# OpenTallas memory compiler (tools/mem_compiler), ASAP7 abstract view, track-aligned v2 (build_aligned_v2.py)
VERSION 5.7 ;
BUSBITCHARS "[]" ;
DIVIDERCHAR "/" ;
PROPERTYDEFINITIONS
  MACRO width INTEGER ;
  MACRO depth INTEGER ;
  MACRO banks INTEGER ;
END PROPERTYDEFINITIONS
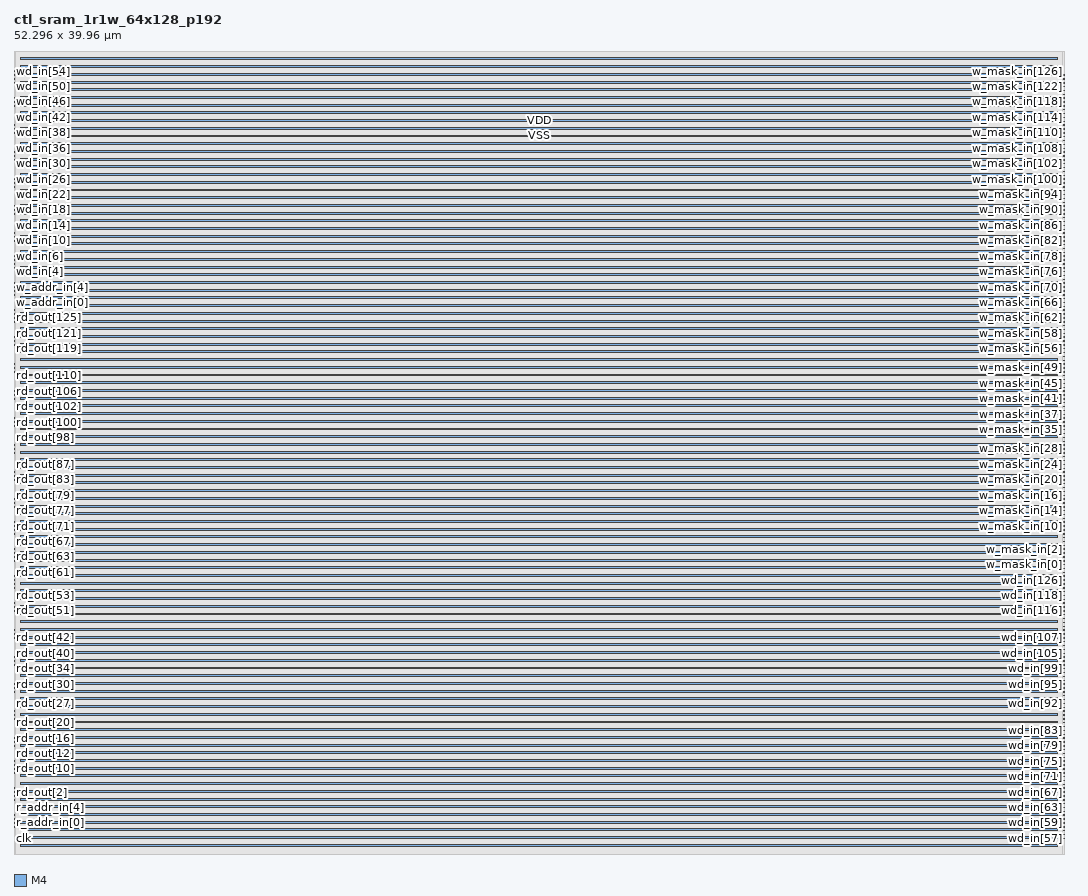
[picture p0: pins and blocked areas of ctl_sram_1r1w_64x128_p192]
MACRO ctl_sram_1r1w_64x128_p192
  PROPERTY width 128 ;
  PROPERTY depth 64 ;
  PROPERTY banks 1 ;
  FOREIGN ctl_sram_1r1w_64x128_p192 0 0 ;
  SYMMETRY X Y ;
  SIZE 52.296 BY 39.960 ;
  CLASS BLOCK ;
  PIN clk
    DIRECTION INPUT ;
    USE CLOCK ;
    SHAPE ABUTMENT ;
    PORT
      LAYER M4 ;
      RECT 0.000 0.768 0.024 0.792 ;
    END
  END clk
  PIN r_ce_in
    DIRECTION INPUT ;
    USE SIGNAL ;
    SHAPE ABUTMENT ;
    PORT
      LAYER M4 ;
      RECT 0.000 0.960 0.024 0.984 ;
    END
  END r_ce_in
  PIN r_addr_in[0]
    DIRECTION INPUT ;
    USE SIGNAL ;
    SHAPE ABUTMENT ;
    PORT
      LAYER M4 ;
      RECT 0.000 1.152 0.024 1.176 ;
    END
  END r_addr_in[0]
  PIN r_addr_in[1]
    DIRECTION INPUT ;
    USE SIGNAL ;
    SHAPE ABUTMENT ;
    PORT
      LAYER M4 ;
      RECT 0.000 1.344 0.024 1.368 ;
    END
  END r_addr_in[1]
  PIN r_addr_in[2]
    DIRECTION INPUT ;
    USE SIGNAL ;
    SHAPE ABUTMENT ;
    PORT
      LAYER M4 ;
      RECT 0.000 1.536 0.024 1.560 ;
    END
  END r_addr_in[2]
  PIN r_addr_in[3]
    DIRECTION INPUT ;
    USE SIGNAL ;
    SHAPE ABUTMENT ;
    PORT
      LAYER M4 ;
      RECT 0.000 1.728 0.024 1.752 ;
    END
  END r_addr_in[3]
  PIN r_addr_in[4]
    DIRECTION INPUT ;
    USE SIGNAL ;
    SHAPE ABUTMENT ;
    PORT
      LAYER M4 ;
      RECT 0.000 1.920 0.024 1.944 ;
    END
  END r_addr_in[4]
  PIN r_addr_in[5]
    DIRECTION INPUT ;
    USE SIGNAL ;
    SHAPE ABUTMENT ;
    PORT
      LAYER M4 ;
      RECT 0.000 2.112 0.024 2.136 ;
    END
  END r_addr_in[5]
  PIN rd_out[0]
    DIRECTION OUTPUT ;
    USE SIGNAL ;
    SHAPE ABUTMENT ;
    PORT
      LAYER M4 ;
      RECT 0.000 2.304 0.024 2.328 ;
    END
  END rd_out[0]
  PIN rd_out[1]
    DIRECTION OUTPUT ;
    USE SIGNAL ;
    SHAPE ABUTMENT ;
    PORT
      LAYER M4 ;
      RECT 0.000 2.496 0.024 2.520 ;
    END
  END rd_out[1]
  PIN rd_out[2]
    DIRECTION OUTPUT ;
    USE SIGNAL ;
    SHAPE ABUTMENT ;
    PORT
      LAYER M4 ;
      RECT 0.000 2.688 0.024 2.712 ;
    END
  END rd_out[2]
  PIN rd_out[3]
    DIRECTION OUTPUT ;
    USE SIGNAL ;
    SHAPE ABUTMENT ;
    PORT
      LAYER M4 ;
      RECT 0.000 2.880 0.024 2.904 ;
    END
  END rd_out[3]
  PIN rd_out[4]
    DIRECTION OUTPUT ;
    USE SIGNAL ;
    SHAPE ABUTMENT ;
    PORT
      LAYER M4 ;
      RECT 0.000 3.072 0.024 3.096 ;
    END
  END rd_out[4]
  PIN rd_out[5]
    DIRECTION OUTPUT ;
    USE SIGNAL ;
    SHAPE ABUTMENT ;
    PORT
      LAYER M4 ;
      RECT 0.000 3.264 0.024 3.288 ;
    END
  END rd_out[5]
  PIN rd_out[6]
    DIRECTION OUTPUT ;
    USE SIGNAL ;
    SHAPE ABUTMENT ;
    PORT
      LAYER M4 ;
      RECT 0.000 3.456 0.024 3.480 ;
    END
  END rd_out[6]
  PIN rd_out[7]
    DIRECTION OUTPUT ;
    USE SIGNAL ;
    SHAPE ABUTMENT ;
    PORT
      LAYER M4 ;
      RECT 0.000 3.648 0.024 3.672 ;
    END
  END rd_out[7]
  PIN rd_out[8]
    DIRECTION OUTPUT ;
    USE SIGNAL ;
    SHAPE ABUTMENT ;
    PORT
      LAYER M4 ;
      RECT 0.000 3.840 0.024 3.864 ;
    END
  END rd_out[8]
  PIN rd_out[9]
    DIRECTION OUTPUT ;
    USE SIGNAL ;
    SHAPE ABUTMENT ;
    PORT
      LAYER M4 ;
      RECT 0.000 4.032 0.024 4.056 ;
    END
  END rd_out[9]
  PIN rd_out[10]
    DIRECTION OUTPUT ;
    USE SIGNAL ;
    SHAPE ABUTMENT ;
    PORT
      LAYER M4 ;
      RECT 0.000 4.224 0.024 4.248 ;
    END
  END rd_out[10]
  PIN rd_out[11]
    DIRECTION OUTPUT ;
    USE SIGNAL ;
    SHAPE ABUTMENT ;
    PORT
      LAYER M4 ;
      RECT 0.000 4.416 0.024 4.440 ;
    END
  END rd_out[11]
  PIN rd_out[12]
    DIRECTION OUTPUT ;
    USE SIGNAL ;
    SHAPE ABUTMENT ;
    PORT
      LAYER M4 ;
      RECT 0.000 4.608 0.024 4.632 ;
    END
  END rd_out[12]
  PIN rd_out[13]
    DIRECTION OUTPUT ;
    USE SIGNAL ;
    SHAPE ABUTMENT ;
    PORT
      LAYER M4 ;
      RECT 0.000 4.800 0.024 4.824 ;
    END
  END rd_out[13]
  PIN rd_out[14]
    DIRECTION OUTPUT ;
    USE SIGNAL ;
    SHAPE ABUTMENT ;
    PORT
      LAYER M4 ;
      RECT 0.000 4.992 0.024 5.016 ;
    END
  END rd_out[14]
  PIN rd_out[15]
    DIRECTION OUTPUT ;
    USE SIGNAL ;
    SHAPE ABUTMENT ;
    PORT
      LAYER M4 ;
      RECT 0.000 5.184 0.024 5.208 ;
    END
  END rd_out[15]
  PIN rd_out[16]
    DIRECTION OUTPUT ;
    USE SIGNAL ;
    SHAPE ABUTMENT ;
    PORT
      LAYER M4 ;
      RECT 0.000 5.376 0.024 5.400 ;
    END
  END rd_out[16]
  PIN rd_out[17]
    DIRECTION OUTPUT ;
    USE SIGNAL ;
    SHAPE ABUTMENT ;
    PORT
      LAYER M4 ;
      RECT 0.000 5.568 0.024 5.592 ;
    END
  END rd_out[17]
  PIN rd_out[18]
    DIRECTION OUTPUT ;
    USE SIGNAL ;
    SHAPE ABUTMENT ;
    PORT
      LAYER M4 ;
      RECT 0.000 5.760 0.024 5.784 ;
    END
  END rd_out[18]
  PIN rd_out[19]
    DIRECTION OUTPUT ;
    USE SIGNAL ;
    SHAPE ABUTMENT ;
    PORT
      LAYER M4 ;
      RECT 0.000 5.952 0.024 5.976 ;
    END
  END rd_out[19]
  PIN rd_out[20]
    DIRECTION OUTPUT ;
    USE SIGNAL ;
    SHAPE ABUTMENT ;
    PORT
      LAYER M4 ;
      RECT 0.000 6.144 0.024 6.168 ;
    END
  END rd_out[20]
  PIN rd_out[21]
    DIRECTION OUTPUT ;
    USE SIGNAL ;
    SHAPE ABUTMENT ;
    PORT
      LAYER M4 ;
      RECT 0.000 6.336 0.024 6.360 ;
    END
  END rd_out[21]
  PIN rd_out[22]
    DIRECTION OUTPUT ;
    USE SIGNAL ;
    SHAPE ABUTMENT ;
    PORT
      LAYER M4 ;
      RECT 0.000 6.528 0.024 6.552 ;
    END
  END rd_out[22]
  PIN rd_out[23]
    DIRECTION OUTPUT ;
    USE SIGNAL ;
    SHAPE ABUTMENT ;
    PORT
      LAYER M4 ;
      RECT 0.000 6.720 0.024 6.744 ;
    END
  END rd_out[23]
  PIN rd_out[24]
    DIRECTION OUTPUT ;
    USE SIGNAL ;
    SHAPE ABUTMENT ;
    PORT
      LAYER M4 ;
      RECT 0.000 6.912 0.024 6.936 ;
    END
  END rd_out[24]
  PIN rd_out[25]
    DIRECTION OUTPUT ;
    USE SIGNAL ;
    SHAPE ABUTMENT ;
    PORT
      LAYER M4 ;
      RECT 0.000 7.104 0.024 7.128 ;
    END
  END rd_out[25]
  PIN rd_out[26]
    DIRECTION OUTPUT ;
    USE SIGNAL ;
    SHAPE ABUTMENT ;
    PORT
      LAYER M4 ;
      RECT 0.000 7.296 0.024 7.320 ;
    END
  END rd_out[26]
  PIN rd_out[27]
    DIRECTION OUTPUT ;
    USE SIGNAL ;
    SHAPE ABUTMENT ;
    PORT
      LAYER M4 ;
      RECT 0.000 7.488 0.024 7.512 ;
    END
  END rd_out[27]
  PIN rd_out[28]
    DIRECTION OUTPUT ;
    USE SIGNAL ;
    SHAPE ABUTMENT ;
    PORT
      LAYER M4 ;
      RECT 0.000 7.680 0.024 7.704 ;
    END
  END rd_out[28]
  PIN rd_out[29]
    DIRECTION OUTPUT ;
    USE SIGNAL ;
    SHAPE ABUTMENT ;
    PORT
      LAYER M4 ;
      RECT 0.000 7.872 0.024 7.896 ;
    END
  END rd_out[29]
  PIN rd_out[30]
    DIRECTION OUTPUT ;
    USE SIGNAL ;
    SHAPE ABUTMENT ;
    PORT
      LAYER M4 ;
      RECT 0.000 8.064 0.024 8.088 ;
    END
  END rd_out[30]
  PIN rd_out[31]
    DIRECTION OUTPUT ;
    USE SIGNAL ;
    SHAPE ABUTMENT ;
    PORT
      LAYER M4 ;
      RECT 0.000 8.256 0.024 8.280 ;
    END
  END rd_out[31]
  PIN rd_out[32]
    DIRECTION OUTPUT ;
    USE SIGNAL ;
    SHAPE ABUTMENT ;
    PORT
      LAYER M4 ;
      RECT 0.000 8.448 0.024 8.472 ;
    END
  END rd_out[32]
  PIN rd_out[33]
    DIRECTION OUTPUT ;
    USE SIGNAL ;
    SHAPE ABUTMENT ;
    PORT
      LAYER M4 ;
      RECT 0.000 8.640 0.024 8.664 ;
    END
  END rd_out[33]
  PIN rd_out[34]
    DIRECTION OUTPUT ;
    USE SIGNAL ;
    SHAPE ABUTMENT ;
    PORT
      LAYER M4 ;
      RECT 0.000 8.832 0.024 8.856 ;
    END
  END rd_out[34]
  PIN rd_out[35]
    DIRECTION OUTPUT ;
    USE SIGNAL ;
    SHAPE ABUTMENT ;
    PORT
      LAYER M4 ;
      RECT 0.000 9.024 0.024 9.048 ;
    END
  END rd_out[35]
  PIN rd_out[36]
    DIRECTION OUTPUT ;
    USE SIGNAL ;
    SHAPE ABUTMENT ;
    PORT
      LAYER M4 ;
      RECT 0.000 9.216 0.024 9.240 ;
    END
  END rd_out[36]
  PIN rd_out[37]
    DIRECTION OUTPUT ;
    USE SIGNAL ;
    SHAPE ABUTMENT ;
    PORT
      LAYER M4 ;
      RECT 0.000 9.408 0.024 9.432 ;
    END
  END rd_out[37]
  PIN rd_out[38]
    DIRECTION OUTPUT ;
    USE SIGNAL ;
    SHAPE ABUTMENT ;
    PORT
      LAYER M4 ;
      RECT 0.000 9.600 0.024 9.624 ;
    END
  END rd_out[38]
  PIN rd_out[39]
    DIRECTION OUTPUT ;
    USE SIGNAL ;
    SHAPE ABUTMENT ;
    PORT
      LAYER M4 ;
      RECT 0.000 9.792 0.024 9.816 ;
    END
  END rd_out[39]
  PIN rd_out[40]
    DIRECTION OUTPUT ;
    USE SIGNAL ;
    SHAPE ABUTMENT ;
    PORT
      LAYER M4 ;
      RECT 0.000 9.984 0.024 10.008 ;
    END
  END rd_out[40]
  PIN rd_out[41]
    DIRECTION OUTPUT ;
    USE SIGNAL ;
    SHAPE ABUTMENT ;
    PORT
      LAYER M4 ;
      RECT 0.000 10.176 0.024 10.200 ;
    END
  END rd_out[41]
  PIN rd_out[42]
    DIRECTION OUTPUT ;
    USE SIGNAL ;
    SHAPE ABUTMENT ;
    PORT
      LAYER M4 ;
      RECT 0.000 10.368 0.024 10.392 ;
    END
  END rd_out[42]
  PIN rd_out[43]
    DIRECTION OUTPUT ;
    USE SIGNAL ;
    SHAPE ABUTMENT ;
    PORT
      LAYER M4 ;
      RECT 0.000 10.560 0.024 10.584 ;
    END
  END rd_out[43]
  PIN rd_out[44]
    DIRECTION OUTPUT ;
    USE SIGNAL ;
    SHAPE ABUTMENT ;
    PORT
      LAYER M4 ;
      RECT 0.000 10.752 0.024 10.776 ;
    END
  END rd_out[44]
  PIN rd_out[45]
    DIRECTION OUTPUT ;
    USE SIGNAL ;
    SHAPE ABUTMENT ;
    PORT
      LAYER M4 ;
      RECT 0.000 10.944 0.024 10.968 ;
    END
  END rd_out[45]
  PIN rd_out[46]
    DIRECTION OUTPUT ;
    USE SIGNAL ;
    SHAPE ABUTMENT ;
    PORT
      LAYER M4 ;
      RECT 0.000 11.136 0.024 11.160 ;
    END
  END rd_out[46]
  PIN rd_out[47]
    DIRECTION OUTPUT ;
    USE SIGNAL ;
    SHAPE ABUTMENT ;
    PORT
      LAYER M4 ;
      RECT 0.000 11.328 0.024 11.352 ;
    END
  END rd_out[47]
  PIN rd_out[48]
    DIRECTION OUTPUT ;
    USE SIGNAL ;
    SHAPE ABUTMENT ;
    PORT
      LAYER M4 ;
      RECT 0.000 11.520 0.024 11.544 ;
    END
  END rd_out[48]
  PIN rd_out[49]
    DIRECTION OUTPUT ;
    USE SIGNAL ;
    SHAPE ABUTMENT ;
    PORT
      LAYER M4 ;
      RECT 0.000 11.712 0.024 11.736 ;
    END
  END rd_out[49]
  PIN rd_out[50]
    DIRECTION OUTPUT ;
    USE SIGNAL ;
    SHAPE ABUTMENT ;
    PORT
      LAYER M4 ;
      RECT 0.000 11.904 0.024 11.928 ;
    END
  END rd_out[50]
  PIN rd_out[51]
    DIRECTION OUTPUT ;
    USE SIGNAL ;
    SHAPE ABUTMENT ;
    PORT
      LAYER M4 ;
      RECT 0.000 12.096 0.024 12.120 ;
    END
  END rd_out[51]
  PIN rd_out[52]
    DIRECTION OUTPUT ;
    USE SIGNAL ;
    SHAPE ABUTMENT ;
    PORT
      LAYER M4 ;
      RECT 0.000 12.288 0.024 12.312 ;
    END
  END rd_out[52]
  PIN rd_out[53]
    DIRECTION OUTPUT ;
    USE SIGNAL ;
    SHAPE ABUTMENT ;
    PORT
      LAYER M4 ;
      RECT 0.000 12.480 0.024 12.504 ;
    END
  END rd_out[53]
  PIN rd_out[54]
    DIRECTION OUTPUT ;
    USE SIGNAL ;
    SHAPE ABUTMENT ;
    PORT
      LAYER M4 ;
      RECT 0.000 12.672 0.024 12.696 ;
    END
  END rd_out[54]
  PIN rd_out[55]
    DIRECTION OUTPUT ;
    USE SIGNAL ;
    SHAPE ABUTMENT ;
    PORT
      LAYER M4 ;
      RECT 0.000 12.864 0.024 12.888 ;
    END
  END rd_out[55]
  PIN rd_out[56]
    DIRECTION OUTPUT ;
    USE SIGNAL ;
    SHAPE ABUTMENT ;
    PORT
      LAYER M4 ;
      RECT 0.000 13.056 0.024 13.080 ;
    END
  END rd_out[56]
  PIN rd_out[57]
    DIRECTION OUTPUT ;
    USE SIGNAL ;
    SHAPE ABUTMENT ;
    PORT
      LAYER M4 ;
      RECT 0.000 13.248 0.024 13.272 ;
    END
  END rd_out[57]
  PIN rd_out[58]
    DIRECTION OUTPUT ;
    USE SIGNAL ;
    SHAPE ABUTMENT ;
    PORT
      LAYER M4 ;
      RECT 0.000 13.440 0.024 13.464 ;
    END
  END rd_out[58]
  PIN rd_out[59]
    DIRECTION OUTPUT ;
    USE SIGNAL ;
    SHAPE ABUTMENT ;
    PORT
      LAYER M4 ;
      RECT 0.000 13.632 0.024 13.656 ;
    END
  END rd_out[59]
  PIN rd_out[60]
    DIRECTION OUTPUT ;
    USE SIGNAL ;
    SHAPE ABUTMENT ;
    PORT
      LAYER M4 ;
      RECT 0.000 13.824 0.024 13.848 ;
    END
  END rd_out[60]
  PIN rd_out[61]
    DIRECTION OUTPUT ;
    USE SIGNAL ;
    SHAPE ABUTMENT ;
    PORT
      LAYER M4 ;
      RECT 0.000 14.016 0.024 14.040 ;
    END
  END rd_out[61]
  PIN rd_out[62]
    DIRECTION OUTPUT ;
    USE SIGNAL ;
    SHAPE ABUTMENT ;
    PORT
      LAYER M4 ;
      RECT 0.000 14.208 0.024 14.232 ;
    END
  END rd_out[62]
  PIN rd_out[63]
    DIRECTION OUTPUT ;
    USE SIGNAL ;
    SHAPE ABUTMENT ;
    PORT
      LAYER M4 ;
      RECT 0.000 14.400 0.024 14.424 ;
    END
  END rd_out[63]
  PIN rd_out[64]
    DIRECTION OUTPUT ;
    USE SIGNAL ;
    SHAPE ABUTMENT ;
    PORT
      LAYER M4 ;
      RECT 0.000 14.592 0.024 14.616 ;
    END
  END rd_out[64]
  PIN rd_out[65]
    DIRECTION OUTPUT ;
    USE SIGNAL ;
    SHAPE ABUTMENT ;
    PORT
      LAYER M4 ;
      RECT 0.000 14.784 0.024 14.808 ;
    END
  END rd_out[65]
  PIN rd_out[66]
    DIRECTION OUTPUT ;
    USE SIGNAL ;
    SHAPE ABUTMENT ;
    PORT
      LAYER M4 ;
      RECT 0.000 14.976 0.024 15.000 ;
    END
  END rd_out[66]
  PIN rd_out[67]
    DIRECTION OUTPUT ;
    USE SIGNAL ;
    SHAPE ABUTMENT ;
    PORT
      LAYER M4 ;
      RECT 0.000 15.168 0.024 15.192 ;
    END
  END rd_out[67]
  PIN rd_out[68]
    DIRECTION OUTPUT ;
    USE SIGNAL ;
    SHAPE ABUTMENT ;
    PORT
      LAYER M4 ;
      RECT 0.000 15.360 0.024 15.384 ;
    END
  END rd_out[68]
  PIN rd_out[69]
    DIRECTION OUTPUT ;
    USE SIGNAL ;
    SHAPE ABUTMENT ;
    PORT
      LAYER M4 ;
      RECT 0.000 15.552 0.024 15.576 ;
    END
  END rd_out[69]
  PIN rd_out[70]
    DIRECTION OUTPUT ;
    USE SIGNAL ;
    SHAPE ABUTMENT ;
    PORT
      LAYER M4 ;
      RECT 0.000 15.744 0.024 15.768 ;
    END
  END rd_out[70]
  PIN rd_out[71]
    DIRECTION OUTPUT ;
    USE SIGNAL ;
    SHAPE ABUTMENT ;
    PORT
      LAYER M4 ;
      RECT 0.000 15.936 0.024 15.960 ;
    END
  END rd_out[71]
  PIN rd_out[72]
    DIRECTION OUTPUT ;
    USE SIGNAL ;
    SHAPE ABUTMENT ;
    PORT
      LAYER M4 ;
      RECT 0.000 16.128 0.024 16.152 ;
    END
  END rd_out[72]
  PIN rd_out[73]
    DIRECTION OUTPUT ;
    USE SIGNAL ;
    SHAPE ABUTMENT ;
    PORT
      LAYER M4 ;
      RECT 0.000 16.320 0.024 16.344 ;
    END
  END rd_out[73]
  PIN rd_out[74]
    DIRECTION OUTPUT ;
    USE SIGNAL ;
    SHAPE ABUTMENT ;
    PORT
      LAYER M4 ;
      RECT 0.000 16.512 0.024 16.536 ;
    END
  END rd_out[74]
  PIN rd_out[75]
    DIRECTION OUTPUT ;
    USE SIGNAL ;
    SHAPE ABUTMENT ;
    PORT
      LAYER M4 ;
      RECT 0.000 16.704 0.024 16.728 ;
    END
  END rd_out[75]
  PIN rd_out[76]
    DIRECTION OUTPUT ;
    USE SIGNAL ;
    SHAPE ABUTMENT ;
    PORT
      LAYER M4 ;
      RECT 0.000 16.896 0.024 16.920 ;
    END
  END rd_out[76]
  PIN rd_out[77]
    DIRECTION OUTPUT ;
    USE SIGNAL ;
    SHAPE ABUTMENT ;
    PORT
      LAYER M4 ;
      RECT 0.000 17.088 0.024 17.112 ;
    END
  END rd_out[77]
  PIN rd_out[78]
    DIRECTION OUTPUT ;
    USE SIGNAL ;
    SHAPE ABUTMENT ;
    PORT
      LAYER M4 ;
      RECT 0.000 17.280 0.024 17.304 ;
    END
  END rd_out[78]
  PIN rd_out[79]
    DIRECTION OUTPUT ;
    USE SIGNAL ;
    SHAPE ABUTMENT ;
    PORT
      LAYER M4 ;
      RECT 0.000 17.472 0.024 17.496 ;
    END
  END rd_out[79]
  PIN rd_out[80]
    DIRECTION OUTPUT ;
    USE SIGNAL ;
    SHAPE ABUTMENT ;
    PORT
      LAYER M4 ;
      RECT 0.000 17.664 0.024 17.688 ;
    END
  END rd_out[80]
  PIN rd_out[81]
    DIRECTION OUTPUT ;
    USE SIGNAL ;
    SHAPE ABUTMENT ;
    PORT
      LAYER M4 ;
      RECT 0.000 17.856 0.024 17.880 ;
    END
  END rd_out[81]
  PIN rd_out[82]
    DIRECTION OUTPUT ;
    USE SIGNAL ;
    SHAPE ABUTMENT ;
    PORT
      LAYER M4 ;
      RECT 0.000 18.048 0.024 18.072 ;
    END
  END rd_out[82]
  PIN rd_out[83]
    DIRECTION OUTPUT ;
    USE SIGNAL ;
    SHAPE ABUTMENT ;
    PORT
      LAYER M4 ;
      RECT 0.000 18.240 0.024 18.264 ;
    END
  END rd_out[83]
  PIN rd_out[84]
    DIRECTION OUTPUT ;
    USE SIGNAL ;
    SHAPE ABUTMENT ;
    PORT
      LAYER M4 ;
      RECT 0.000 18.432 0.024 18.456 ;
    END
  END rd_out[84]
  PIN rd_out[85]
    DIRECTION OUTPUT ;
    USE SIGNAL ;
    SHAPE ABUTMENT ;
    PORT
      LAYER M4 ;
      RECT 0.000 18.624 0.024 18.648 ;
    END
  END rd_out[85]
  PIN rd_out[86]
    DIRECTION OUTPUT ;
    USE SIGNAL ;
    SHAPE ABUTMENT ;
    PORT
      LAYER M4 ;
      RECT 0.000 18.816 0.024 18.840 ;
    END
  END rd_out[86]
  PIN rd_out[87]
    DIRECTION OUTPUT ;
    USE SIGNAL ;
    SHAPE ABUTMENT ;
    PORT
      LAYER M4 ;
      RECT 0.000 19.008 0.024 19.032 ;
    END
  END rd_out[87]
  PIN rd_out[88]
    DIRECTION OUTPUT ;
    USE SIGNAL ;
    SHAPE ABUTMENT ;
    PORT
      LAYER M4 ;
      RECT 0.000 19.200 0.024 19.224 ;
    END
  END rd_out[88]
  PIN rd_out[89]
    DIRECTION OUTPUT ;
    USE SIGNAL ;
    SHAPE ABUTMENT ;
    PORT
      LAYER M4 ;
      RECT 0.000 19.392 0.024 19.416 ;
    END
  END rd_out[89]
  PIN rd_out[90]
    DIRECTION OUTPUT ;
    USE SIGNAL ;
    SHAPE ABUTMENT ;
    PORT
      LAYER M4 ;
      RECT 0.000 19.584 0.024 19.608 ;
    END
  END rd_out[90]
  PIN rd_out[91]
    DIRECTION OUTPUT ;
    USE SIGNAL ;
    SHAPE ABUTMENT ;
    PORT
      LAYER M4 ;
      RECT 0.000 19.776 0.024 19.800 ;
    END
  END rd_out[91]
  PIN rd_out[92]
    DIRECTION OUTPUT ;
    USE SIGNAL ;
    SHAPE ABUTMENT ;
    PORT
      LAYER M4 ;
      RECT 0.000 19.968 0.024 19.992 ;
    END
  END rd_out[92]
  PIN rd_out[93]
    DIRECTION OUTPUT ;
    USE SIGNAL ;
    SHAPE ABUTMENT ;
    PORT
      LAYER M4 ;
      RECT 0.000 20.160 0.024 20.184 ;
    END
  END rd_out[93]
  PIN rd_out[94]
    DIRECTION OUTPUT ;
    USE SIGNAL ;
    SHAPE ABUTMENT ;
    PORT
      LAYER M4 ;
      RECT 0.000 20.352 0.024 20.376 ;
    END
  END rd_out[94]
  PIN rd_out[95]
    DIRECTION OUTPUT ;
    USE SIGNAL ;
    SHAPE ABUTMENT ;
    PORT
      LAYER M4 ;
      RECT 0.000 20.544 0.024 20.568 ;
    END
  END rd_out[95]
  PIN rd_out[96]
    DIRECTION OUTPUT ;
    USE SIGNAL ;
    SHAPE ABUTMENT ;
    PORT
      LAYER M4 ;
      RECT 0.000 20.736 0.024 20.760 ;
    END
  END rd_out[96]
  PIN rd_out[97]
    DIRECTION OUTPUT ;
    USE SIGNAL ;
    SHAPE ABUTMENT ;
    PORT
      LAYER M4 ;
      RECT 0.000 20.928 0.024 20.952 ;
    END
  END rd_out[97]
  PIN rd_out[98]
    DIRECTION OUTPUT ;
    USE SIGNAL ;
    SHAPE ABUTMENT ;
    PORT
      LAYER M4 ;
      RECT 0.000 21.120 0.024 21.144 ;
    END
  END rd_out[98]
  PIN rd_out[99]
    DIRECTION OUTPUT ;
    USE SIGNAL ;
    SHAPE ABUTMENT ;
    PORT
      LAYER M4 ;
      RECT 0.000 21.312 0.024 21.336 ;
    END
  END rd_out[99]
  PIN rd_out[100]
    DIRECTION OUTPUT ;
    USE SIGNAL ;
    SHAPE ABUTMENT ;
    PORT
      LAYER M4 ;
      RECT 0.000 21.504 0.024 21.528 ;
    END
  END rd_out[100]
  PIN rd_out[101]
    DIRECTION OUTPUT ;
    USE SIGNAL ;
    SHAPE ABUTMENT ;
    PORT
      LAYER M4 ;
      RECT 0.000 21.696 0.024 21.720 ;
    END
  END rd_out[101]
  PIN rd_out[102]
    DIRECTION OUTPUT ;
    USE SIGNAL ;
    SHAPE ABUTMENT ;
    PORT
      LAYER M4 ;
      RECT 0.000 21.888 0.024 21.912 ;
    END
  END rd_out[102]
  PIN rd_out[103]
    DIRECTION OUTPUT ;
    USE SIGNAL ;
    SHAPE ABUTMENT ;
    PORT
      LAYER M4 ;
      RECT 0.000 22.080 0.024 22.104 ;
    END
  END rd_out[103]
  PIN rd_out[104]
    DIRECTION OUTPUT ;
    USE SIGNAL ;
    SHAPE ABUTMENT ;
    PORT
      LAYER M4 ;
      RECT 0.000 22.272 0.024 22.296 ;
    END
  END rd_out[104]
  PIN rd_out[105]
    DIRECTION OUTPUT ;
    USE SIGNAL ;
    SHAPE ABUTMENT ;
    PORT
      LAYER M4 ;
      RECT 0.000 22.464 0.024 22.488 ;
    END
  END rd_out[105]
  PIN rd_out[106]
    DIRECTION OUTPUT ;
    USE SIGNAL ;
    SHAPE ABUTMENT ;
    PORT
      LAYER M4 ;
      RECT 0.000 22.656 0.024 22.680 ;
    END
  END rd_out[106]
  PIN rd_out[107]
    DIRECTION OUTPUT ;
    USE SIGNAL ;
    SHAPE ABUTMENT ;
    PORT
      LAYER M4 ;
      RECT 0.000 22.848 0.024 22.872 ;
    END
  END rd_out[107]
  PIN rd_out[108]
    DIRECTION OUTPUT ;
    USE SIGNAL ;
    SHAPE ABUTMENT ;
    PORT
      LAYER M4 ;
      RECT 0.000 23.040 0.024 23.064 ;
    END
  END rd_out[108]
  PIN rd_out[109]
    DIRECTION OUTPUT ;
    USE SIGNAL ;
    SHAPE ABUTMENT ;
    PORT
      LAYER M4 ;
      RECT 0.000 23.232 0.024 23.256 ;
    END
  END rd_out[109]
  PIN rd_out[110]
    DIRECTION OUTPUT ;
    USE SIGNAL ;
    SHAPE ABUTMENT ;
    PORT
      LAYER M4 ;
      RECT 0.000 23.424 0.024 23.448 ;
    END
  END rd_out[110]
  PIN rd_out[111]
    DIRECTION OUTPUT ;
    USE SIGNAL ;
    SHAPE ABUTMENT ;
    PORT
      LAYER M4 ;
      RECT 0.000 23.616 0.024 23.640 ;
    END
  END rd_out[111]
  PIN rd_out[112]
    DIRECTION OUTPUT ;
    USE SIGNAL ;
    SHAPE ABUTMENT ;
    PORT
      LAYER M4 ;
      RECT 0.000 23.808 0.024 23.832 ;
    END
  END rd_out[112]
  PIN rd_out[113]
    DIRECTION OUTPUT ;
    USE SIGNAL ;
    SHAPE ABUTMENT ;
    PORT
      LAYER M4 ;
      RECT 0.000 24.000 0.024 24.024 ;
    END
  END rd_out[113]
  PIN rd_out[114]
    DIRECTION OUTPUT ;
    USE SIGNAL ;
    SHAPE ABUTMENT ;
    PORT
      LAYER M4 ;
      RECT 0.000 24.192 0.024 24.216 ;
    END
  END rd_out[114]
  PIN rd_out[115]
    DIRECTION OUTPUT ;
    USE SIGNAL ;
    SHAPE ABUTMENT ;
    PORT
      LAYER M4 ;
      RECT 0.000 24.384 0.024 24.408 ;
    END
  END rd_out[115]
  PIN rd_out[116]
    DIRECTION OUTPUT ;
    USE SIGNAL ;
    SHAPE ABUTMENT ;
    PORT
      LAYER M4 ;
      RECT 0.000 24.576 0.024 24.600 ;
    END
  END rd_out[116]
  PIN rd_out[117]
    DIRECTION OUTPUT ;
    USE SIGNAL ;
    SHAPE ABUTMENT ;
    PORT
      LAYER M4 ;
      RECT 0.000 24.768 0.024 24.792 ;
    END
  END rd_out[117]
  PIN rd_out[118]
    DIRECTION OUTPUT ;
    USE SIGNAL ;
    SHAPE ABUTMENT ;
    PORT
      LAYER M4 ;
      RECT 0.000 24.960 0.024 24.984 ;
    END
  END rd_out[118]
  PIN rd_out[119]
    DIRECTION OUTPUT ;
    USE SIGNAL ;
    SHAPE ABUTMENT ;
    PORT
      LAYER M4 ;
      RECT 0.000 25.152 0.024 25.176 ;
    END
  END rd_out[119]
  PIN rd_out[120]
    DIRECTION OUTPUT ;
    USE SIGNAL ;
    SHAPE ABUTMENT ;
    PORT
      LAYER M4 ;
      RECT 0.000 25.344 0.024 25.368 ;
    END
  END rd_out[120]
  PIN rd_out[121]
    DIRECTION OUTPUT ;
    USE SIGNAL ;
    SHAPE ABUTMENT ;
    PORT
      LAYER M4 ;
      RECT 0.000 25.536 0.024 25.560 ;
    END
  END rd_out[121]
  PIN rd_out[122]
    DIRECTION OUTPUT ;
    USE SIGNAL ;
    SHAPE ABUTMENT ;
    PORT
      LAYER M4 ;
      RECT 0.000 25.728 0.024 25.752 ;
    END
  END rd_out[122]
  PIN rd_out[123]
    DIRECTION OUTPUT ;
    USE SIGNAL ;
    SHAPE ABUTMENT ;
    PORT
      LAYER M4 ;
      RECT 0.000 25.920 0.024 25.944 ;
    END
  END rd_out[123]
  PIN rd_out[124]
    DIRECTION OUTPUT ;
    USE SIGNAL ;
    SHAPE ABUTMENT ;
    PORT
      LAYER M4 ;
      RECT 0.000 26.112 0.024 26.136 ;
    END
  END rd_out[124]
  PIN rd_out[125]
    DIRECTION OUTPUT ;
    USE SIGNAL ;
    SHAPE ABUTMENT ;
    PORT
      LAYER M4 ;
      RECT 0.000 26.304 0.024 26.328 ;
    END
  END rd_out[125]
  PIN rd_out[126]
    DIRECTION OUTPUT ;
    USE SIGNAL ;
    SHAPE ABUTMENT ;
    PORT
      LAYER M4 ;
      RECT 0.000 26.496 0.024 26.520 ;
    END
  END rd_out[126]
  PIN rd_out[127]
    DIRECTION OUTPUT ;
    USE SIGNAL ;
    SHAPE ABUTMENT ;
    PORT
      LAYER M4 ;
      RECT 0.000 26.688 0.024 26.712 ;
    END
  END rd_out[127]
  PIN w_ce_in
    DIRECTION INPUT ;
    USE SIGNAL ;
    SHAPE ABUTMENT ;
    PORT
      LAYER M4 ;
      RECT 0.000 26.880 0.024 26.904 ;
    END
  END w_ce_in
  PIN w_addr_in[0]
    DIRECTION INPUT ;
    USE SIGNAL ;
    SHAPE ABUTMENT ;
    PORT
      LAYER M4 ;
      RECT 0.000 27.072 0.024 27.096 ;
    END
  END w_addr_in[0]
  PIN w_addr_in[1]
    DIRECTION INPUT ;
    USE SIGNAL ;
    SHAPE ABUTMENT ;
    PORT
      LAYER M4 ;
      RECT 0.000 27.264 0.024 27.288 ;
    END
  END w_addr_in[1]
  PIN w_addr_in[2]
    DIRECTION INPUT ;
    USE SIGNAL ;
    SHAPE ABUTMENT ;
    PORT
      LAYER M4 ;
      RECT 0.000 27.456 0.024 27.480 ;
    END
  END w_addr_in[2]
  PIN w_addr_in[3]
    DIRECTION INPUT ;
    USE SIGNAL ;
    SHAPE ABUTMENT ;
    PORT
      LAYER M4 ;
      RECT 0.000 27.648 0.024 27.672 ;
    END
  END w_addr_in[3]
  PIN w_addr_in[4]
    DIRECTION INPUT ;
    USE SIGNAL ;
    SHAPE ABUTMENT ;
    PORT
      LAYER M4 ;
      RECT 0.000 27.840 0.024 27.864 ;
    END
  END w_addr_in[4]
  PIN w_addr_in[5]
    DIRECTION INPUT ;
    USE SIGNAL ;
    SHAPE ABUTMENT ;
    PORT
      LAYER M4 ;
      RECT 0.000 28.032 0.024 28.056 ;
    END
  END w_addr_in[5]
  PIN wd_in[0]
    DIRECTION INPUT ;
    USE SIGNAL ;
    SHAPE ABUTMENT ;
    PORT
      LAYER M4 ;
      RECT 0.000 28.224 0.024 28.248 ;
    END
  END wd_in[0]
  PIN wd_in[1]
    DIRECTION INPUT ;
    USE SIGNAL ;
    SHAPE ABUTMENT ;
    PORT
      LAYER M4 ;
      RECT 0.000 28.416 0.024 28.440 ;
    END
  END wd_in[1]
  PIN wd_in[2]
    DIRECTION INPUT ;
    USE SIGNAL ;
    SHAPE ABUTMENT ;
    PORT
      LAYER M4 ;
      RECT 0.000 28.608 0.024 28.632 ;
    END
  END wd_in[2]
  PIN wd_in[3]
    DIRECTION INPUT ;
    USE SIGNAL ;
    SHAPE ABUTMENT ;
    PORT
      LAYER M4 ;
      RECT 0.000 28.800 0.024 28.824 ;
    END
  END wd_in[3]
  PIN wd_in[4]
    DIRECTION INPUT ;
    USE SIGNAL ;
    SHAPE ABUTMENT ;
    PORT
      LAYER M4 ;
      RECT 0.000 28.992 0.024 29.016 ;
    END
  END wd_in[4]
  PIN wd_in[5]
    DIRECTION INPUT ;
    USE SIGNAL ;
    SHAPE ABUTMENT ;
    PORT
      LAYER M4 ;
      RECT 0.000 29.184 0.024 29.208 ;
    END
  END wd_in[5]
  PIN wd_in[6]
    DIRECTION INPUT ;
    USE SIGNAL ;
    SHAPE ABUTMENT ;
    PORT
      LAYER M4 ;
      RECT 0.000 29.376 0.024 29.400 ;
    END
  END wd_in[6]
  PIN wd_in[7]
    DIRECTION INPUT ;
    USE SIGNAL ;
    SHAPE ABUTMENT ;
    PORT
      LAYER M4 ;
      RECT 0.000 29.568 0.024 29.592 ;
    END
  END wd_in[7]
  PIN wd_in[8]
    DIRECTION INPUT ;
    USE SIGNAL ;
    SHAPE ABUTMENT ;
    PORT
      LAYER M4 ;
      RECT 0.000 29.760 0.024 29.784 ;
    END
  END wd_in[8]
  PIN wd_in[9]
    DIRECTION INPUT ;
    USE SIGNAL ;
    SHAPE ABUTMENT ;
    PORT
      LAYER M4 ;
      RECT 0.000 29.952 0.024 29.976 ;
    END
  END wd_in[9]
  PIN wd_in[10]
    DIRECTION INPUT ;
    USE SIGNAL ;
    SHAPE ABUTMENT ;
    PORT
      LAYER M4 ;
      RECT 0.000 30.144 0.024 30.168 ;
    END
  END wd_in[10]
  PIN wd_in[11]
    DIRECTION INPUT ;
    USE SIGNAL ;
    SHAPE ABUTMENT ;
    PORT
      LAYER M4 ;
      RECT 0.000 30.336 0.024 30.360 ;
    END
  END wd_in[11]
  PIN wd_in[12]
    DIRECTION INPUT ;
    USE SIGNAL ;
    SHAPE ABUTMENT ;
    PORT
      LAYER M4 ;
      RECT 0.000 30.528 0.024 30.552 ;
    END
  END wd_in[12]
  PIN wd_in[13]
    DIRECTION INPUT ;
    USE SIGNAL ;
    SHAPE ABUTMENT ;
    PORT
      LAYER M4 ;
      RECT 0.000 30.720 0.024 30.744 ;
    END
  END wd_in[13]
  PIN wd_in[14]
    DIRECTION INPUT ;
    USE SIGNAL ;
    SHAPE ABUTMENT ;
    PORT
      LAYER M4 ;
      RECT 0.000 30.912 0.024 30.936 ;
    END
  END wd_in[14]
  PIN wd_in[15]
    DIRECTION INPUT ;
    USE SIGNAL ;
    SHAPE ABUTMENT ;
    PORT
      LAYER M4 ;
      RECT 0.000 31.104 0.024 31.128 ;
    END
  END wd_in[15]
  PIN wd_in[16]
    DIRECTION INPUT ;
    USE SIGNAL ;
    SHAPE ABUTMENT ;
    PORT
      LAYER M4 ;
      RECT 0.000 31.296 0.024 31.320 ;
    END
  END wd_in[16]
  PIN wd_in[17]
    DIRECTION INPUT ;
    USE SIGNAL ;
    SHAPE ABUTMENT ;
    PORT
      LAYER M4 ;
      RECT 0.000 31.488 0.024 31.512 ;
    END
  END wd_in[17]
  PIN wd_in[18]
    DIRECTION INPUT ;
    USE SIGNAL ;
    SHAPE ABUTMENT ;
    PORT
      LAYER M4 ;
      RECT 0.000 31.680 0.024 31.704 ;
    END
  END wd_in[18]
  PIN wd_in[19]
    DIRECTION INPUT ;
    USE SIGNAL ;
    SHAPE ABUTMENT ;
    PORT
      LAYER M4 ;
      RECT 0.000 31.872 0.024 31.896 ;
    END
  END wd_in[19]
  PIN wd_in[20]
    DIRECTION INPUT ;
    USE SIGNAL ;
    SHAPE ABUTMENT ;
    PORT
      LAYER M4 ;
      RECT 0.000 32.064 0.024 32.088 ;
    END
  END wd_in[20]
  PIN wd_in[21]
    DIRECTION INPUT ;
    USE SIGNAL ;
    SHAPE ABUTMENT ;
    PORT
      LAYER M4 ;
      RECT 0.000 32.256 0.024 32.280 ;
    END
  END wd_in[21]
  PIN wd_in[22]
    DIRECTION INPUT ;
    USE SIGNAL ;
    SHAPE ABUTMENT ;
    PORT
      LAYER M4 ;
      RECT 0.000 32.448 0.024 32.472 ;
    END
  END wd_in[22]
  PIN wd_in[23]
    DIRECTION INPUT ;
    USE SIGNAL ;
    SHAPE ABUTMENT ;
    PORT
      LAYER M4 ;
      RECT 0.000 32.640 0.024 32.664 ;
    END
  END wd_in[23]
  PIN wd_in[24]
    DIRECTION INPUT ;
    USE SIGNAL ;
    SHAPE ABUTMENT ;
    PORT
      LAYER M4 ;
      RECT 0.000 32.832 0.024 32.856 ;
    END
  END wd_in[24]
  PIN wd_in[25]
    DIRECTION INPUT ;
    USE SIGNAL ;
    SHAPE ABUTMENT ;
    PORT
      LAYER M4 ;
      RECT 0.000 33.024 0.024 33.048 ;
    END
  END wd_in[25]
  PIN wd_in[26]
    DIRECTION INPUT ;
    USE SIGNAL ;
    SHAPE ABUTMENT ;
    PORT
      LAYER M4 ;
      RECT 0.000 33.216 0.024 33.240 ;
    END
  END wd_in[26]
  PIN wd_in[27]
    DIRECTION INPUT ;
    USE SIGNAL ;
    SHAPE ABUTMENT ;
    PORT
      LAYER M4 ;
      RECT 0.000 33.408 0.024 33.432 ;
    END
  END wd_in[27]
  PIN wd_in[28]
    DIRECTION INPUT ;
    USE SIGNAL ;
    SHAPE ABUTMENT ;
    PORT
      LAYER M4 ;
      RECT 0.000 33.600 0.024 33.624 ;
    END
  END wd_in[28]
  PIN wd_in[29]
    DIRECTION INPUT ;
    USE SIGNAL ;
    SHAPE ABUTMENT ;
    PORT
      LAYER M4 ;
      RECT 0.000 33.792 0.024 33.816 ;
    END
  END wd_in[29]
  PIN wd_in[30]
    DIRECTION INPUT ;
    USE SIGNAL ;
    SHAPE ABUTMENT ;
    PORT
      LAYER M4 ;
      RECT 0.000 33.984 0.024 34.008 ;
    END
  END wd_in[30]
  PIN wd_in[31]
    DIRECTION INPUT ;
    USE SIGNAL ;
    SHAPE ABUTMENT ;
    PORT
      LAYER M4 ;
      RECT 0.000 34.176 0.024 34.200 ;
    END
  END wd_in[31]
  PIN wd_in[32]
    DIRECTION INPUT ;
    USE SIGNAL ;
    SHAPE ABUTMENT ;
    PORT
      LAYER M4 ;
      RECT 0.000 34.368 0.024 34.392 ;
    END
  END wd_in[32]
  PIN wd_in[33]
    DIRECTION INPUT ;
    USE SIGNAL ;
    SHAPE ABUTMENT ;
    PORT
      LAYER M4 ;
      RECT 0.000 34.560 0.024 34.584 ;
    END
  END wd_in[33]
  PIN wd_in[34]
    DIRECTION INPUT ;
    USE SIGNAL ;
    SHAPE ABUTMENT ;
    PORT
      LAYER M4 ;
      RECT 0.000 34.752 0.024 34.776 ;
    END
  END wd_in[34]
  PIN wd_in[35]
    DIRECTION INPUT ;
    USE SIGNAL ;
    SHAPE ABUTMENT ;
    PORT
      LAYER M4 ;
      RECT 0.000 34.944 0.024 34.968 ;
    END
  END wd_in[35]
  PIN wd_in[36]
    DIRECTION INPUT ;
    USE SIGNAL ;
    SHAPE ABUTMENT ;
    PORT
      LAYER M4 ;
      RECT 0.000 35.136 0.024 35.160 ;
    END
  END wd_in[36]
  PIN wd_in[37]
    DIRECTION INPUT ;
    USE SIGNAL ;
    SHAPE ABUTMENT ;
    PORT
      LAYER M4 ;
      RECT 0.000 35.328 0.024 35.352 ;
    END
  END wd_in[37]
  PIN wd_in[38]
    DIRECTION INPUT ;
    USE SIGNAL ;
    SHAPE ABUTMENT ;
    PORT
      LAYER M4 ;
      RECT 0.000 35.520 0.024 35.544 ;
    END
  END wd_in[38]
  PIN wd_in[39]
    DIRECTION INPUT ;
    USE SIGNAL ;
    SHAPE ABUTMENT ;
    PORT
      LAYER M4 ;
      RECT 0.000 35.712 0.024 35.736 ;
    END
  END wd_in[39]
  PIN wd_in[40]
    DIRECTION INPUT ;
    USE SIGNAL ;
    SHAPE ABUTMENT ;
    PORT
      LAYER M4 ;
      RECT 0.000 35.904 0.024 35.928 ;
    END
  END wd_in[40]
  PIN wd_in[41]
    DIRECTION INPUT ;
    USE SIGNAL ;
    SHAPE ABUTMENT ;
    PORT
      LAYER M4 ;
      RECT 0.000 36.096 0.024 36.120 ;
    END
  END wd_in[41]
  PIN wd_in[42]
    DIRECTION INPUT ;
    USE SIGNAL ;
    SHAPE ABUTMENT ;
    PORT
      LAYER M4 ;
      RECT 0.000 36.288 0.024 36.312 ;
    END
  END wd_in[42]
  PIN wd_in[43]
    DIRECTION INPUT ;
    USE SIGNAL ;
    SHAPE ABUTMENT ;
    PORT
      LAYER M4 ;
      RECT 0.000 36.480 0.024 36.504 ;
    END
  END wd_in[43]
  PIN wd_in[44]
    DIRECTION INPUT ;
    USE SIGNAL ;
    SHAPE ABUTMENT ;
    PORT
      LAYER M4 ;
      RECT 0.000 36.672 0.024 36.696 ;
    END
  END wd_in[44]
  PIN wd_in[45]
    DIRECTION INPUT ;
    USE SIGNAL ;
    SHAPE ABUTMENT ;
    PORT
      LAYER M4 ;
      RECT 0.000 36.864 0.024 36.888 ;
    END
  END wd_in[45]
  PIN wd_in[46]
    DIRECTION INPUT ;
    USE SIGNAL ;
    SHAPE ABUTMENT ;
    PORT
      LAYER M4 ;
      RECT 0.000 37.056 0.024 37.080 ;
    END
  END wd_in[46]
  PIN wd_in[47]
    DIRECTION INPUT ;
    USE SIGNAL ;
    SHAPE ABUTMENT ;
    PORT
      LAYER M4 ;
      RECT 0.000 37.248 0.024 37.272 ;
    END
  END wd_in[47]
  PIN wd_in[48]
    DIRECTION INPUT ;
    USE SIGNAL ;
    SHAPE ABUTMENT ;
    PORT
      LAYER M4 ;
      RECT 0.000 37.440 0.024 37.464 ;
    END
  END wd_in[48]
  PIN wd_in[49]
    DIRECTION INPUT ;
    USE SIGNAL ;
    SHAPE ABUTMENT ;
    PORT
      LAYER M4 ;
      RECT 0.000 37.632 0.024 37.656 ;
    END
  END wd_in[49]
  PIN wd_in[50]
    DIRECTION INPUT ;
    USE SIGNAL ;
    SHAPE ABUTMENT ;
    PORT
      LAYER M4 ;
      RECT 0.000 37.824 0.024 37.848 ;
    END
  END wd_in[50]
  PIN wd_in[51]
    DIRECTION INPUT ;
    USE SIGNAL ;
    SHAPE ABUTMENT ;
    PORT
      LAYER M4 ;
      RECT 0.000 38.016 0.024 38.040 ;
    END
  END wd_in[51]
  PIN wd_in[52]
    DIRECTION INPUT ;
    USE SIGNAL ;
    SHAPE ABUTMENT ;
    PORT
      LAYER M4 ;
      RECT 0.000 38.208 0.024 38.232 ;
    END
  END wd_in[52]
  PIN wd_in[53]
    DIRECTION INPUT ;
    USE SIGNAL ;
    SHAPE ABUTMENT ;
    PORT
      LAYER M4 ;
      RECT 0.000 38.400 0.024 38.424 ;
    END
  END wd_in[53]
  PIN wd_in[54]
    DIRECTION INPUT ;
    USE SIGNAL ;
    SHAPE ABUTMENT ;
    PORT
      LAYER M4 ;
      RECT 0.000 38.592 0.024 38.616 ;
    END
  END wd_in[54]
  PIN wd_in[55]
    DIRECTION INPUT ;
    USE SIGNAL ;
    SHAPE ABUTMENT ;
    PORT
      LAYER M4 ;
      RECT 0.000 38.784 0.024 38.808 ;
    END
  END wd_in[55]
  PIN wd_in[56]
    DIRECTION INPUT ;
    USE SIGNAL ;
    SHAPE ABUTMENT ;
    PORT
      LAYER M4 ;
      RECT 0.000 38.976 0.024 39.000 ;
    END
  END wd_in[56]
  PIN wd_in[57]
    DIRECTION INPUT ;
    USE SIGNAL ;
    SHAPE ABUTMENT ;
    PORT
      LAYER M4 ;
      RECT 52.272 0.768 52.296 0.792 ;
    END
  END wd_in[57]
  PIN wd_in[58]
    DIRECTION INPUT ;
    USE SIGNAL ;
    SHAPE ABUTMENT ;
    PORT
      LAYER M4 ;
      RECT 52.272 0.960 52.296 0.984 ;
    END
  END wd_in[58]
  PIN wd_in[59]
    DIRECTION INPUT ;
    USE SIGNAL ;
    SHAPE ABUTMENT ;
    PORT
      LAYER M4 ;
      RECT 52.272 1.152 52.296 1.176 ;
    END
  END wd_in[59]
  PIN wd_in[60]
    DIRECTION INPUT ;
    USE SIGNAL ;
    SHAPE ABUTMENT ;
    PORT
      LAYER M4 ;
      RECT 52.272 1.344 52.296 1.368 ;
    END
  END wd_in[60]
  PIN wd_in[61]
    DIRECTION INPUT ;
    USE SIGNAL ;
    SHAPE ABUTMENT ;
    PORT
      LAYER M4 ;
      RECT 52.272 1.536 52.296 1.560 ;
    END
  END wd_in[61]
  PIN wd_in[62]
    DIRECTION INPUT ;
    USE SIGNAL ;
    SHAPE ABUTMENT ;
    PORT
      LAYER M4 ;
      RECT 52.272 1.728 52.296 1.752 ;
    END
  END wd_in[62]
  PIN wd_in[63]
    DIRECTION INPUT ;
    USE SIGNAL ;
    SHAPE ABUTMENT ;
    PORT
      LAYER M4 ;
      RECT 52.272 1.920 52.296 1.944 ;
    END
  END wd_in[63]
  PIN wd_in[64]
    DIRECTION INPUT ;
    USE SIGNAL ;
    SHAPE ABUTMENT ;
    PORT
      LAYER M4 ;
      RECT 52.272 2.112 52.296 2.136 ;
    END
  END wd_in[64]
  PIN wd_in[65]
    DIRECTION INPUT ;
    USE SIGNAL ;
    SHAPE ABUTMENT ;
    PORT
      LAYER M4 ;
      RECT 52.272 2.304 52.296 2.328 ;
    END
  END wd_in[65]
  PIN wd_in[66]
    DIRECTION INPUT ;
    USE SIGNAL ;
    SHAPE ABUTMENT ;
    PORT
      LAYER M4 ;
      RECT 52.272 2.496 52.296 2.520 ;
    END
  END wd_in[66]
  PIN wd_in[67]
    DIRECTION INPUT ;
    USE SIGNAL ;
    SHAPE ABUTMENT ;
    PORT
      LAYER M4 ;
      RECT 52.272 2.688 52.296 2.712 ;
    END
  END wd_in[67]
  PIN wd_in[68]
    DIRECTION INPUT ;
    USE SIGNAL ;
    SHAPE ABUTMENT ;
    PORT
      LAYER M4 ;
      RECT 52.272 2.880 52.296 2.904 ;
    END
  END wd_in[68]
  PIN wd_in[69]
    DIRECTION INPUT ;
    USE SIGNAL ;
    SHAPE ABUTMENT ;
    PORT
      LAYER M4 ;
      RECT 52.272 3.072 52.296 3.096 ;
    END
  END wd_in[69]
  PIN wd_in[70]
    DIRECTION INPUT ;
    USE SIGNAL ;
    SHAPE ABUTMENT ;
    PORT
      LAYER M4 ;
      RECT 52.272 3.264 52.296 3.288 ;
    END
  END wd_in[70]
  PIN wd_in[71]
    DIRECTION INPUT ;
    USE SIGNAL ;
    SHAPE ABUTMENT ;
    PORT
      LAYER M4 ;
      RECT 52.272 3.456 52.296 3.480 ;
    END
  END wd_in[71]
  PIN wd_in[72]
    DIRECTION INPUT ;
    USE SIGNAL ;
    SHAPE ABUTMENT ;
    PORT
      LAYER M4 ;
      RECT 52.272 3.648 52.296 3.672 ;
    END
  END wd_in[72]
  PIN wd_in[73]
    DIRECTION INPUT ;
    USE SIGNAL ;
    SHAPE ABUTMENT ;
    PORT
      LAYER M4 ;
      RECT 52.272 3.840 52.296 3.864 ;
    END
  END wd_in[73]
  PIN wd_in[74]
    DIRECTION INPUT ;
    USE SIGNAL ;
    SHAPE ABUTMENT ;
    PORT
      LAYER M4 ;
      RECT 52.272 4.032 52.296 4.056 ;
    END
  END wd_in[74]
  PIN wd_in[75]
    DIRECTION INPUT ;
    USE SIGNAL ;
    SHAPE ABUTMENT ;
    PORT
      LAYER M4 ;
      RECT 52.272 4.224 52.296 4.248 ;
    END
  END wd_in[75]
  PIN wd_in[76]
    DIRECTION INPUT ;
    USE SIGNAL ;
    SHAPE ABUTMENT ;
    PORT
      LAYER M4 ;
      RECT 52.272 4.416 52.296 4.440 ;
    END
  END wd_in[76]
  PIN wd_in[77]
    DIRECTION INPUT ;
    USE SIGNAL ;
    SHAPE ABUTMENT ;
    PORT
      LAYER M4 ;
      RECT 52.272 4.608 52.296 4.632 ;
    END
  END wd_in[77]
  PIN wd_in[78]
    DIRECTION INPUT ;
    USE SIGNAL ;
    SHAPE ABUTMENT ;
    PORT
      LAYER M4 ;
      RECT 52.272 4.800 52.296 4.824 ;
    END
  END wd_in[78]
  PIN wd_in[79]
    DIRECTION INPUT ;
    USE SIGNAL ;
    SHAPE ABUTMENT ;
    PORT
      LAYER M4 ;
      RECT 52.272 4.992 52.296 5.016 ;
    END
  END wd_in[79]
  PIN wd_in[80]
    DIRECTION INPUT ;
    USE SIGNAL ;
    SHAPE ABUTMENT ;
    PORT
      LAYER M4 ;
      RECT 52.272 5.184 52.296 5.208 ;
    END
  END wd_in[80]
  PIN wd_in[81]
    DIRECTION INPUT ;
    USE SIGNAL ;
    SHAPE ABUTMENT ;
    PORT
      LAYER M4 ;
      RECT 52.272 5.376 52.296 5.400 ;
    END
  END wd_in[81]
  PIN wd_in[82]
    DIRECTION INPUT ;
    USE SIGNAL ;
    SHAPE ABUTMENT ;
    PORT
      LAYER M4 ;
      RECT 52.272 5.568 52.296 5.592 ;
    END
  END wd_in[82]
  PIN wd_in[83]
    DIRECTION INPUT ;
    USE SIGNAL ;
    SHAPE ABUTMENT ;
    PORT
      LAYER M4 ;
      RECT 52.272 5.760 52.296 5.784 ;
    END
  END wd_in[83]
  PIN wd_in[84]
    DIRECTION INPUT ;
    USE SIGNAL ;
    SHAPE ABUTMENT ;
    PORT
      LAYER M4 ;
      RECT 52.272 5.952 52.296 5.976 ;
    END
  END wd_in[84]
  PIN wd_in[85]
    DIRECTION INPUT ;
    USE SIGNAL ;
    SHAPE ABUTMENT ;
    PORT
      LAYER M4 ;
      RECT 52.272 6.144 52.296 6.168 ;
    END
  END wd_in[85]
  PIN wd_in[86]
    DIRECTION INPUT ;
    USE SIGNAL ;
    SHAPE ABUTMENT ;
    PORT
      LAYER M4 ;
      RECT 52.272 6.336 52.296 6.360 ;
    END
  END wd_in[86]
  PIN wd_in[87]
    DIRECTION INPUT ;
    USE SIGNAL ;
    SHAPE ABUTMENT ;
    PORT
      LAYER M4 ;
      RECT 52.272 6.528 52.296 6.552 ;
    END
  END wd_in[87]
  PIN wd_in[88]
    DIRECTION INPUT ;
    USE SIGNAL ;
    SHAPE ABUTMENT ;
    PORT
      LAYER M4 ;
      RECT 52.272 6.720 52.296 6.744 ;
    END
  END wd_in[88]
  PIN wd_in[89]
    DIRECTION INPUT ;
    USE SIGNAL ;
    SHAPE ABUTMENT ;
    PORT
      LAYER M4 ;
      RECT 52.272 6.912 52.296 6.936 ;
    END
  END wd_in[89]
  PIN wd_in[90]
    DIRECTION INPUT ;
    USE SIGNAL ;
    SHAPE ABUTMENT ;
    PORT
      LAYER M4 ;
      RECT 52.272 7.104 52.296 7.128 ;
    END
  END wd_in[90]
  PIN wd_in[91]
    DIRECTION INPUT ;
    USE SIGNAL ;
    SHAPE ABUTMENT ;
    PORT
      LAYER M4 ;
      RECT 52.272 7.296 52.296 7.320 ;
    END
  END wd_in[91]
  PIN wd_in[92]
    DIRECTION INPUT ;
    USE SIGNAL ;
    SHAPE ABUTMENT ;
    PORT
      LAYER M4 ;
      RECT 52.272 7.488 52.296 7.512 ;
    END
  END wd_in[92]
  PIN wd_in[93]
    DIRECTION INPUT ;
    USE SIGNAL ;
    SHAPE ABUTMENT ;
    PORT
      LAYER M4 ;
      RECT 52.272 7.680 52.296 7.704 ;
    END
  END wd_in[93]
  PIN wd_in[94]
    DIRECTION INPUT ;
    USE SIGNAL ;
    SHAPE ABUTMENT ;
    PORT
      LAYER M4 ;
      RECT 52.272 7.872 52.296 7.896 ;
    END
  END wd_in[94]
  PIN wd_in[95]
    DIRECTION INPUT ;
    USE SIGNAL ;
    SHAPE ABUTMENT ;
    PORT
      LAYER M4 ;
      RECT 52.272 8.064 52.296 8.088 ;
    END
  END wd_in[95]
  PIN wd_in[96]
    DIRECTION INPUT ;
    USE SIGNAL ;
    SHAPE ABUTMENT ;
    PORT
      LAYER M4 ;
      RECT 52.272 8.256 52.296 8.280 ;
    END
  END wd_in[96]
  PIN wd_in[97]
    DIRECTION INPUT ;
    USE SIGNAL ;
    SHAPE ABUTMENT ;
    PORT
      LAYER M4 ;
      RECT 52.272 8.448 52.296 8.472 ;
    END
  END wd_in[97]
  PIN wd_in[98]
    DIRECTION INPUT ;
    USE SIGNAL ;
    SHAPE ABUTMENT ;
    PORT
      LAYER M4 ;
      RECT 52.272 8.640 52.296 8.664 ;
    END
  END wd_in[98]
  PIN wd_in[99]
    DIRECTION INPUT ;
    USE SIGNAL ;
    SHAPE ABUTMENT ;
    PORT
      LAYER M4 ;
      RECT 52.272 8.832 52.296 8.856 ;
    END
  END wd_in[99]
  PIN wd_in[100]
    DIRECTION INPUT ;
    USE SIGNAL ;
    SHAPE ABUTMENT ;
    PORT
      LAYER M4 ;
      RECT 52.272 9.024 52.296 9.048 ;
    END
  END wd_in[100]
  PIN wd_in[101]
    DIRECTION INPUT ;
    USE SIGNAL ;
    SHAPE ABUTMENT ;
    PORT
      LAYER M4 ;
      RECT 52.272 9.216 52.296 9.240 ;
    END
  END wd_in[101]
  PIN wd_in[102]
    DIRECTION INPUT ;
    USE SIGNAL ;
    SHAPE ABUTMENT ;
    PORT
      LAYER M4 ;
      RECT 52.272 9.408 52.296 9.432 ;
    END
  END wd_in[102]
  PIN wd_in[103]
    DIRECTION INPUT ;
    USE SIGNAL ;
    SHAPE ABUTMENT ;
    PORT
      LAYER M4 ;
      RECT 52.272 9.600 52.296 9.624 ;
    END
  END wd_in[103]
  PIN wd_in[104]
    DIRECTION INPUT ;
    USE SIGNAL ;
    SHAPE ABUTMENT ;
    PORT
      LAYER M4 ;
      RECT 52.272 9.792 52.296 9.816 ;
    END
  END wd_in[104]
  PIN wd_in[105]
    DIRECTION INPUT ;
    USE SIGNAL ;
    SHAPE ABUTMENT ;
    PORT
      LAYER M4 ;
      RECT 52.272 9.984 52.296 10.008 ;
    END
  END wd_in[105]
  PIN wd_in[106]
    DIRECTION INPUT ;
    USE SIGNAL ;
    SHAPE ABUTMENT ;
    PORT
      LAYER M4 ;
      RECT 52.272 10.176 52.296 10.200 ;
    END
  END wd_in[106]
  PIN wd_in[107]
    DIRECTION INPUT ;
    USE SIGNAL ;
    SHAPE ABUTMENT ;
    PORT
      LAYER M4 ;
      RECT 52.272 10.368 52.296 10.392 ;
    END
  END wd_in[107]
  PIN wd_in[108]
    DIRECTION INPUT ;
    USE SIGNAL ;
    SHAPE ABUTMENT ;
    PORT
      LAYER M4 ;
      RECT 52.272 10.560 52.296 10.584 ;
    END
  END wd_in[108]
  PIN wd_in[109]
    DIRECTION INPUT ;
    USE SIGNAL ;
    SHAPE ABUTMENT ;
    PORT
      LAYER M4 ;
      RECT 52.272 10.752 52.296 10.776 ;
    END
  END wd_in[109]
  PIN wd_in[110]
    DIRECTION INPUT ;
    USE SIGNAL ;
    SHAPE ABUTMENT ;
    PORT
      LAYER M4 ;
      RECT 52.272 10.944 52.296 10.968 ;
    END
  END wd_in[110]
  PIN wd_in[111]
    DIRECTION INPUT ;
    USE SIGNAL ;
    SHAPE ABUTMENT ;
    PORT
      LAYER M4 ;
      RECT 52.272 11.136 52.296 11.160 ;
    END
  END wd_in[111]
  PIN wd_in[112]
    DIRECTION INPUT ;
    USE SIGNAL ;
    SHAPE ABUTMENT ;
    PORT
      LAYER M4 ;
      RECT 52.272 11.328 52.296 11.352 ;
    END
  END wd_in[112]
  PIN wd_in[113]
    DIRECTION INPUT ;
    USE SIGNAL ;
    SHAPE ABUTMENT ;
    PORT
      LAYER M4 ;
      RECT 52.272 11.520 52.296 11.544 ;
    END
  END wd_in[113]
  PIN wd_in[114]
    DIRECTION INPUT ;
    USE SIGNAL ;
    SHAPE ABUTMENT ;
    PORT
      LAYER M4 ;
      RECT 52.272 11.712 52.296 11.736 ;
    END
  END wd_in[114]
  PIN wd_in[115]
    DIRECTION INPUT ;
    USE SIGNAL ;
    SHAPE ABUTMENT ;
    PORT
      LAYER M4 ;
      RECT 52.272 11.904 52.296 11.928 ;
    END
  END wd_in[115]
  PIN wd_in[116]
    DIRECTION INPUT ;
    USE SIGNAL ;
    SHAPE ABUTMENT ;
    PORT
      LAYER M4 ;
      RECT 52.272 12.096 52.296 12.120 ;
    END
  END wd_in[116]
  PIN wd_in[117]
    DIRECTION INPUT ;
    USE SIGNAL ;
    SHAPE ABUTMENT ;
    PORT
      LAYER M4 ;
      RECT 52.272 12.288 52.296 12.312 ;
    END
  END wd_in[117]
  PIN wd_in[118]
    DIRECTION INPUT ;
    USE SIGNAL ;
    SHAPE ABUTMENT ;
    PORT
      LAYER M4 ;
      RECT 52.272 12.480 52.296 12.504 ;
    END
  END wd_in[118]
  PIN wd_in[119]
    DIRECTION INPUT ;
    USE SIGNAL ;
    SHAPE ABUTMENT ;
    PORT
      LAYER M4 ;
      RECT 52.272 12.672 52.296 12.696 ;
    END
  END wd_in[119]
  PIN wd_in[120]
    DIRECTION INPUT ;
    USE SIGNAL ;
    SHAPE ABUTMENT ;
    PORT
      LAYER M4 ;
      RECT 52.272 12.864 52.296 12.888 ;
    END
  END wd_in[120]
  PIN wd_in[121]
    DIRECTION INPUT ;
    USE SIGNAL ;
    SHAPE ABUTMENT ;
    PORT
      LAYER M4 ;
      RECT 52.272 13.056 52.296 13.080 ;
    END
  END wd_in[121]
  PIN wd_in[122]
    DIRECTION INPUT ;
    USE SIGNAL ;
    SHAPE ABUTMENT ;
    PORT
      LAYER M4 ;
      RECT 52.272 13.248 52.296 13.272 ;
    END
  END wd_in[122]
  PIN wd_in[123]
    DIRECTION INPUT ;
    USE SIGNAL ;
    SHAPE ABUTMENT ;
    PORT
      LAYER M4 ;
      RECT 52.272 13.440 52.296 13.464 ;
    END
  END wd_in[123]
  PIN wd_in[124]
    DIRECTION INPUT ;
    USE SIGNAL ;
    SHAPE ABUTMENT ;
    PORT
      LAYER M4 ;
      RECT 52.272 13.632 52.296 13.656 ;
    END
  END wd_in[124]
  PIN wd_in[125]
    DIRECTION INPUT ;
    USE SIGNAL ;
    SHAPE ABUTMENT ;
    PORT
      LAYER M4 ;
      RECT 52.272 13.824 52.296 13.848 ;
    END
  END wd_in[125]
  PIN wd_in[126]
    DIRECTION INPUT ;
    USE SIGNAL ;
    SHAPE ABUTMENT ;
    PORT
      LAYER M4 ;
      RECT 52.272 14.016 52.296 14.040 ;
    END
  END wd_in[126]
  PIN wd_in[127]
    DIRECTION INPUT ;
    USE SIGNAL ;
    SHAPE ABUTMENT ;
    PORT
      LAYER M4 ;
      RECT 52.272 14.208 52.296 14.232 ;
    END
  END wd_in[127]
  PIN w_mask_in[0]
    DIRECTION INPUT ;
    USE SIGNAL ;
    SHAPE ABUTMENT ;
    PORT
      LAYER M4 ;
      RECT 52.272 14.400 52.296 14.424 ;
    END
  END w_mask_in[0]
  PIN w_mask_in[1]
    DIRECTION INPUT ;
    USE SIGNAL ;
    SHAPE ABUTMENT ;
    PORT
      LAYER M4 ;
      RECT 52.272 14.592 52.296 14.616 ;
    END
  END w_mask_in[1]
  PIN w_mask_in[2]
    DIRECTION INPUT ;
    USE SIGNAL ;
    SHAPE ABUTMENT ;
    PORT
      LAYER M4 ;
      RECT 52.272 14.784 52.296 14.808 ;
    END
  END w_mask_in[2]
  PIN w_mask_in[3]
    DIRECTION INPUT ;
    USE SIGNAL ;
    SHAPE ABUTMENT ;
    PORT
      LAYER M4 ;
      RECT 52.272 14.976 52.296 15.000 ;
    END
  END w_mask_in[3]
  PIN w_mask_in[4]
    DIRECTION INPUT ;
    USE SIGNAL ;
    SHAPE ABUTMENT ;
    PORT
      LAYER M4 ;
      RECT 52.272 15.168 52.296 15.192 ;
    END
  END w_mask_in[4]
  PIN w_mask_in[5]
    DIRECTION INPUT ;
    USE SIGNAL ;
    SHAPE ABUTMENT ;
    PORT
      LAYER M4 ;
      RECT 52.272 15.360 52.296 15.384 ;
    END
  END w_mask_in[5]
  PIN w_mask_in[6]
    DIRECTION INPUT ;
    USE SIGNAL ;
    SHAPE ABUTMENT ;
    PORT
      LAYER M4 ;
      RECT 52.272 15.552 52.296 15.576 ;
    END
  END w_mask_in[6]
  PIN w_mask_in[7]
    DIRECTION INPUT ;
    USE SIGNAL ;
    SHAPE ABUTMENT ;
    PORT
      LAYER M4 ;
      RECT 52.272 15.744 52.296 15.768 ;
    END
  END w_mask_in[7]
  PIN w_mask_in[8]
    DIRECTION INPUT ;
    USE SIGNAL ;
    SHAPE ABUTMENT ;
    PORT
      LAYER M4 ;
      RECT 52.272 15.936 52.296 15.960 ;
    END
  END w_mask_in[8]
  PIN w_mask_in[9]
    DIRECTION INPUT ;
    USE SIGNAL ;
    SHAPE ABUTMENT ;
    PORT
      LAYER M4 ;
      RECT 52.272 16.128 52.296 16.152 ;
    END
  END w_mask_in[9]
  PIN w_mask_in[10]
    DIRECTION INPUT ;
    USE SIGNAL ;
    SHAPE ABUTMENT ;
    PORT
      LAYER M4 ;
      RECT 52.272 16.320 52.296 16.344 ;
    END
  END w_mask_in[10]
  PIN w_mask_in[11]
    DIRECTION INPUT ;
    USE SIGNAL ;
    SHAPE ABUTMENT ;
    PORT
      LAYER M4 ;
      RECT 52.272 16.512 52.296 16.536 ;
    END
  END w_mask_in[11]
  PIN w_mask_in[12]
    DIRECTION INPUT ;
    USE SIGNAL ;
    SHAPE ABUTMENT ;
    PORT
      LAYER M4 ;
      RECT 52.272 16.704 52.296 16.728 ;
    END
  END w_mask_in[12]
  PIN w_mask_in[13]
    DIRECTION INPUT ;
    USE SIGNAL ;
    SHAPE ABUTMENT ;
    PORT
      LAYER M4 ;
      RECT 52.272 16.896 52.296 16.920 ;
    END
  END w_mask_in[13]
  PIN w_mask_in[14]
    DIRECTION INPUT ;
    USE SIGNAL ;
    SHAPE ABUTMENT ;
    PORT
      LAYER M4 ;
      RECT 52.272 17.088 52.296 17.112 ;
    END
  END w_mask_in[14]
  PIN w_mask_in[15]
    DIRECTION INPUT ;
    USE SIGNAL ;
    SHAPE ABUTMENT ;
    PORT
      LAYER M4 ;
      RECT 52.272 17.280 52.296 17.304 ;
    END
  END w_mask_in[15]
  PIN w_mask_in[16]
    DIRECTION INPUT ;
    USE SIGNAL ;
    SHAPE ABUTMENT ;
    PORT
      LAYER M4 ;
      RECT 52.272 17.472 52.296 17.496 ;
    END
  END w_mask_in[16]
  PIN w_mask_in[17]
    DIRECTION INPUT ;
    USE SIGNAL ;
    SHAPE ABUTMENT ;
    PORT
      LAYER M4 ;
      RECT 52.272 17.664 52.296 17.688 ;
    END
  END w_mask_in[17]
  PIN w_mask_in[18]
    DIRECTION INPUT ;
    USE SIGNAL ;
    SHAPE ABUTMENT ;
    PORT
      LAYER M4 ;
      RECT 52.272 17.856 52.296 17.880 ;
    END
  END w_mask_in[18]
  PIN w_mask_in[19]
    DIRECTION INPUT ;
    USE SIGNAL ;
    SHAPE ABUTMENT ;
    PORT
      LAYER M4 ;
      RECT 52.272 18.048 52.296 18.072 ;
    END
  END w_mask_in[19]
  PIN w_mask_in[20]
    DIRECTION INPUT ;
    USE SIGNAL ;
    SHAPE ABUTMENT ;
    PORT
      LAYER M4 ;
      RECT 52.272 18.240 52.296 18.264 ;
    END
  END w_mask_in[20]
  PIN w_mask_in[21]
    DIRECTION INPUT ;
    USE SIGNAL ;
    SHAPE ABUTMENT ;
    PORT
      LAYER M4 ;
      RECT 52.272 18.432 52.296 18.456 ;
    END
  END w_mask_in[21]
  PIN w_mask_in[22]
    DIRECTION INPUT ;
    USE SIGNAL ;
    SHAPE ABUTMENT ;
    PORT
      LAYER M4 ;
      RECT 52.272 18.624 52.296 18.648 ;
    END
  END w_mask_in[22]
  PIN w_mask_in[23]
    DIRECTION INPUT ;
    USE SIGNAL ;
    SHAPE ABUTMENT ;
    PORT
      LAYER M4 ;
      RECT 52.272 18.816 52.296 18.840 ;
    END
  END w_mask_in[23]
  PIN w_mask_in[24]
    DIRECTION INPUT ;
    USE SIGNAL ;
    SHAPE ABUTMENT ;
    PORT
      LAYER M4 ;
      RECT 52.272 19.008 52.296 19.032 ;
    END
  END w_mask_in[24]
  PIN w_mask_in[25]
    DIRECTION INPUT ;
    USE SIGNAL ;
    SHAPE ABUTMENT ;
    PORT
      LAYER M4 ;
      RECT 52.272 19.200 52.296 19.224 ;
    END
  END w_mask_in[25]
  PIN w_mask_in[26]
    DIRECTION INPUT ;
    USE SIGNAL ;
    SHAPE ABUTMENT ;
    PORT
      LAYER M4 ;
      RECT 52.272 19.392 52.296 19.416 ;
    END
  END w_mask_in[26]
  PIN w_mask_in[27]
    DIRECTION INPUT ;
    USE SIGNAL ;
    SHAPE ABUTMENT ;
    PORT
      LAYER M4 ;
      RECT 52.272 19.584 52.296 19.608 ;
    END
  END w_mask_in[27]
  PIN w_mask_in[28]
    DIRECTION INPUT ;
    USE SIGNAL ;
    SHAPE ABUTMENT ;
    PORT
      LAYER M4 ;
      RECT 52.272 19.776 52.296 19.800 ;
    END
  END w_mask_in[28]
  PIN w_mask_in[29]
    DIRECTION INPUT ;
    USE SIGNAL ;
    SHAPE ABUTMENT ;
    PORT
      LAYER M4 ;
      RECT 52.272 19.968 52.296 19.992 ;
    END
  END w_mask_in[29]
  PIN w_mask_in[30]
    DIRECTION INPUT ;
    USE SIGNAL ;
    SHAPE ABUTMENT ;
    PORT
      LAYER M4 ;
      RECT 52.272 20.160 52.296 20.184 ;
    END
  END w_mask_in[30]
  PIN w_mask_in[31]
    DIRECTION INPUT ;
    USE SIGNAL ;
    SHAPE ABUTMENT ;
    PORT
      LAYER M4 ;
      RECT 52.272 20.352 52.296 20.376 ;
    END
  END w_mask_in[31]
  PIN w_mask_in[32]
    DIRECTION INPUT ;
    USE SIGNAL ;
    SHAPE ABUTMENT ;
    PORT
      LAYER M4 ;
      RECT 52.272 20.544 52.296 20.568 ;
    END
  END w_mask_in[32]
  PIN w_mask_in[33]
    DIRECTION INPUT ;
    USE SIGNAL ;
    SHAPE ABUTMENT ;
    PORT
      LAYER M4 ;
      RECT 52.272 20.736 52.296 20.760 ;
    END
  END w_mask_in[33]
  PIN w_mask_in[34]
    DIRECTION INPUT ;
    USE SIGNAL ;
    SHAPE ABUTMENT ;
    PORT
      LAYER M4 ;
      RECT 52.272 20.928 52.296 20.952 ;
    END
  END w_mask_in[34]
  PIN w_mask_in[35]
    DIRECTION INPUT ;
    USE SIGNAL ;
    SHAPE ABUTMENT ;
    PORT
      LAYER M4 ;
      RECT 52.272 21.120 52.296 21.144 ;
    END
  END w_mask_in[35]
  PIN w_mask_in[36]
    DIRECTION INPUT ;
    USE SIGNAL ;
    SHAPE ABUTMENT ;
    PORT
      LAYER M4 ;
      RECT 52.272 21.312 52.296 21.336 ;
    END
  END w_mask_in[36]
  PIN w_mask_in[37]
    DIRECTION INPUT ;
    USE SIGNAL ;
    SHAPE ABUTMENT ;
    PORT
      LAYER M4 ;
      RECT 52.272 21.504 52.296 21.528 ;
    END
  END w_mask_in[37]
  PIN w_mask_in[38]
    DIRECTION INPUT ;
    USE SIGNAL ;
    SHAPE ABUTMENT ;
    PORT
      LAYER M4 ;
      RECT 52.272 21.696 52.296 21.720 ;
    END
  END w_mask_in[38]
  PIN w_mask_in[39]
    DIRECTION INPUT ;
    USE SIGNAL ;
    SHAPE ABUTMENT ;
    PORT
      LAYER M4 ;
      RECT 52.272 21.888 52.296 21.912 ;
    END
  END w_mask_in[39]
  PIN w_mask_in[40]
    DIRECTION INPUT ;
    USE SIGNAL ;
    SHAPE ABUTMENT ;
    PORT
      LAYER M4 ;
      RECT 52.272 22.080 52.296 22.104 ;
    END
  END w_mask_in[40]
  PIN w_mask_in[41]
    DIRECTION INPUT ;
    USE SIGNAL ;
    SHAPE ABUTMENT ;
    PORT
      LAYER M4 ;
      RECT 52.272 22.272 52.296 22.296 ;
    END
  END w_mask_in[41]
  PIN w_mask_in[42]
    DIRECTION INPUT ;
    USE SIGNAL ;
    SHAPE ABUTMENT ;
    PORT
      LAYER M4 ;
      RECT 52.272 22.464 52.296 22.488 ;
    END
  END w_mask_in[42]
  PIN w_mask_in[43]
    DIRECTION INPUT ;
    USE SIGNAL ;
    SHAPE ABUTMENT ;
    PORT
      LAYER M4 ;
      RECT 52.272 22.656 52.296 22.680 ;
    END
  END w_mask_in[43]
  PIN w_mask_in[44]
    DIRECTION INPUT ;
    USE SIGNAL ;
    SHAPE ABUTMENT ;
    PORT
      LAYER M4 ;
      RECT 52.272 22.848 52.296 22.872 ;
    END
  END w_mask_in[44]
  PIN w_mask_in[45]
    DIRECTION INPUT ;
    USE SIGNAL ;
    SHAPE ABUTMENT ;
    PORT
      LAYER M4 ;
      RECT 52.272 23.040 52.296 23.064 ;
    END
  END w_mask_in[45]
  PIN w_mask_in[46]
    DIRECTION INPUT ;
    USE SIGNAL ;
    SHAPE ABUTMENT ;
    PORT
      LAYER M4 ;
      RECT 52.272 23.232 52.296 23.256 ;
    END
  END w_mask_in[46]
  PIN w_mask_in[47]
    DIRECTION INPUT ;
    USE SIGNAL ;
    SHAPE ABUTMENT ;
    PORT
      LAYER M4 ;
      RECT 52.272 23.424 52.296 23.448 ;
    END
  END w_mask_in[47]
  PIN w_mask_in[48]
    DIRECTION INPUT ;
    USE SIGNAL ;
    SHAPE ABUTMENT ;
    PORT
      LAYER M4 ;
      RECT 52.272 23.616 52.296 23.640 ;
    END
  END w_mask_in[48]
  PIN w_mask_in[49]
    DIRECTION INPUT ;
    USE SIGNAL ;
    SHAPE ABUTMENT ;
    PORT
      LAYER M4 ;
      RECT 52.272 23.808 52.296 23.832 ;
    END
  END w_mask_in[49]
  PIN w_mask_in[50]
    DIRECTION INPUT ;
    USE SIGNAL ;
    SHAPE ABUTMENT ;
    PORT
      LAYER M4 ;
      RECT 52.272 24.000 52.296 24.024 ;
    END
  END w_mask_in[50]
  PIN w_mask_in[51]
    DIRECTION INPUT ;
    USE SIGNAL ;
    SHAPE ABUTMENT ;
    PORT
      LAYER M4 ;
      RECT 52.272 24.192 52.296 24.216 ;
    END
  END w_mask_in[51]
  PIN w_mask_in[52]
    DIRECTION INPUT ;
    USE SIGNAL ;
    SHAPE ABUTMENT ;
    PORT
      LAYER M4 ;
      RECT 52.272 24.384 52.296 24.408 ;
    END
  END w_mask_in[52]
  PIN w_mask_in[53]
    DIRECTION INPUT ;
    USE SIGNAL ;
    SHAPE ABUTMENT ;
    PORT
      LAYER M4 ;
      RECT 52.272 24.576 52.296 24.600 ;
    END
  END w_mask_in[53]
  PIN w_mask_in[54]
    DIRECTION INPUT ;
    USE SIGNAL ;
    SHAPE ABUTMENT ;
    PORT
      LAYER M4 ;
      RECT 52.272 24.768 52.296 24.792 ;
    END
  END w_mask_in[54]
  PIN w_mask_in[55]
    DIRECTION INPUT ;
    USE SIGNAL ;
    SHAPE ABUTMENT ;
    PORT
      LAYER M4 ;
      RECT 52.272 24.960 52.296 24.984 ;
    END
  END w_mask_in[55]
  PIN w_mask_in[56]
    DIRECTION INPUT ;
    USE SIGNAL ;
    SHAPE ABUTMENT ;
    PORT
      LAYER M4 ;
      RECT 52.272 25.152 52.296 25.176 ;
    END
  END w_mask_in[56]
  PIN w_mask_in[57]
    DIRECTION INPUT ;
    USE SIGNAL ;
    SHAPE ABUTMENT ;
    PORT
      LAYER M4 ;
      RECT 52.272 25.344 52.296 25.368 ;
    END
  END w_mask_in[57]
  PIN w_mask_in[58]
    DIRECTION INPUT ;
    USE SIGNAL ;
    SHAPE ABUTMENT ;
    PORT
      LAYER M4 ;
      RECT 52.272 25.536 52.296 25.560 ;
    END
  END w_mask_in[58]
  PIN w_mask_in[59]
    DIRECTION INPUT ;
    USE SIGNAL ;
    SHAPE ABUTMENT ;
    PORT
      LAYER M4 ;
      RECT 52.272 25.728 52.296 25.752 ;
    END
  END w_mask_in[59]
  PIN w_mask_in[60]
    DIRECTION INPUT ;
    USE SIGNAL ;
    SHAPE ABUTMENT ;
    PORT
      LAYER M4 ;
      RECT 52.272 25.920 52.296 25.944 ;
    END
  END w_mask_in[60]
  PIN w_mask_in[61]
    DIRECTION INPUT ;
    USE SIGNAL ;
    SHAPE ABUTMENT ;
    PORT
      LAYER M4 ;
      RECT 52.272 26.112 52.296 26.136 ;
    END
  END w_mask_in[61]
  PIN w_mask_in[62]
    DIRECTION INPUT ;
    USE SIGNAL ;
    SHAPE ABUTMENT ;
    PORT
      LAYER M4 ;
      RECT 52.272 26.304 52.296 26.328 ;
    END
  END w_mask_in[62]
  PIN w_mask_in[63]
    DIRECTION INPUT ;
    USE SIGNAL ;
    SHAPE ABUTMENT ;
    PORT
      LAYER M4 ;
      RECT 52.272 26.496 52.296 26.520 ;
    END
  END w_mask_in[63]
  PIN w_mask_in[64]
    DIRECTION INPUT ;
    USE SIGNAL ;
    SHAPE ABUTMENT ;
    PORT
      LAYER M4 ;
      RECT 52.272 26.688 52.296 26.712 ;
    END
  END w_mask_in[64]
  PIN w_mask_in[65]
    DIRECTION INPUT ;
    USE SIGNAL ;
    SHAPE ABUTMENT ;
    PORT
      LAYER M4 ;
      RECT 52.272 26.880 52.296 26.904 ;
    END
  END w_mask_in[65]
  PIN w_mask_in[66]
    DIRECTION INPUT ;
    USE SIGNAL ;
    SHAPE ABUTMENT ;
    PORT
      LAYER M4 ;
      RECT 52.272 27.072 52.296 27.096 ;
    END
  END w_mask_in[66]
  PIN w_mask_in[67]
    DIRECTION INPUT ;
    USE SIGNAL ;
    SHAPE ABUTMENT ;
    PORT
      LAYER M4 ;
      RECT 52.272 27.264 52.296 27.288 ;
    END
  END w_mask_in[67]
  PIN w_mask_in[68]
    DIRECTION INPUT ;
    USE SIGNAL ;
    SHAPE ABUTMENT ;
    PORT
      LAYER M4 ;
      RECT 52.272 27.456 52.296 27.480 ;
    END
  END w_mask_in[68]
  PIN w_mask_in[69]
    DIRECTION INPUT ;
    USE SIGNAL ;
    SHAPE ABUTMENT ;
    PORT
      LAYER M4 ;
      RECT 52.272 27.648 52.296 27.672 ;
    END
  END w_mask_in[69]
  PIN w_mask_in[70]
    DIRECTION INPUT ;
    USE SIGNAL ;
    SHAPE ABUTMENT ;
    PORT
      LAYER M4 ;
      RECT 52.272 27.840 52.296 27.864 ;
    END
  END w_mask_in[70]
  PIN w_mask_in[71]
    DIRECTION INPUT ;
    USE SIGNAL ;
    SHAPE ABUTMENT ;
    PORT
      LAYER M4 ;
      RECT 52.272 28.032 52.296 28.056 ;
    END
  END w_mask_in[71]
  PIN w_mask_in[72]
    DIRECTION INPUT ;
    USE SIGNAL ;
    SHAPE ABUTMENT ;
    PORT
      LAYER M4 ;
      RECT 52.272 28.224 52.296 28.248 ;
    END
  END w_mask_in[72]
  PIN w_mask_in[73]
    DIRECTION INPUT ;
    USE SIGNAL ;
    SHAPE ABUTMENT ;
    PORT
      LAYER M4 ;
      RECT 52.272 28.416 52.296 28.440 ;
    END
  END w_mask_in[73]
  PIN w_mask_in[74]
    DIRECTION INPUT ;
    USE SIGNAL ;
    SHAPE ABUTMENT ;
    PORT
      LAYER M4 ;
      RECT 52.272 28.608 52.296 28.632 ;
    END
  END w_mask_in[74]
  PIN w_mask_in[75]
    DIRECTION INPUT ;
    USE SIGNAL ;
    SHAPE ABUTMENT ;
    PORT
      LAYER M4 ;
      RECT 52.272 28.800 52.296 28.824 ;
    END
  END w_mask_in[75]
  PIN w_mask_in[76]
    DIRECTION INPUT ;
    USE SIGNAL ;
    SHAPE ABUTMENT ;
    PORT
      LAYER M4 ;
      RECT 52.272 28.992 52.296 29.016 ;
    END
  END w_mask_in[76]
  PIN w_mask_in[77]
    DIRECTION INPUT ;
    USE SIGNAL ;
    SHAPE ABUTMENT ;
    PORT
      LAYER M4 ;
      RECT 52.272 29.184 52.296 29.208 ;
    END
  END w_mask_in[77]
  PIN w_mask_in[78]
    DIRECTION INPUT ;
    USE SIGNAL ;
    SHAPE ABUTMENT ;
    PORT
      LAYER M4 ;
      RECT 52.272 29.376 52.296 29.400 ;
    END
  END w_mask_in[78]
  PIN w_mask_in[79]
    DIRECTION INPUT ;
    USE SIGNAL ;
    SHAPE ABUTMENT ;
    PORT
      LAYER M4 ;
      RECT 52.272 29.568 52.296 29.592 ;
    END
  END w_mask_in[79]
  PIN w_mask_in[80]
    DIRECTION INPUT ;
    USE SIGNAL ;
    SHAPE ABUTMENT ;
    PORT
      LAYER M4 ;
      RECT 52.272 29.760 52.296 29.784 ;
    END
  END w_mask_in[80]
  PIN w_mask_in[81]
    DIRECTION INPUT ;
    USE SIGNAL ;
    SHAPE ABUTMENT ;
    PORT
      LAYER M4 ;
      RECT 52.272 29.952 52.296 29.976 ;
    END
  END w_mask_in[81]
  PIN w_mask_in[82]
    DIRECTION INPUT ;
    USE SIGNAL ;
    SHAPE ABUTMENT ;
    PORT
      LAYER M4 ;
      RECT 52.272 30.144 52.296 30.168 ;
    END
  END w_mask_in[82]
  PIN w_mask_in[83]
    DIRECTION INPUT ;
    USE SIGNAL ;
    SHAPE ABUTMENT ;
    PORT
      LAYER M4 ;
      RECT 52.272 30.336 52.296 30.360 ;
    END
  END w_mask_in[83]
  PIN w_mask_in[84]
    DIRECTION INPUT ;
    USE SIGNAL ;
    SHAPE ABUTMENT ;
    PORT
      LAYER M4 ;
      RECT 52.272 30.528 52.296 30.552 ;
    END
  END w_mask_in[84]
  PIN w_mask_in[85]
    DIRECTION INPUT ;
    USE SIGNAL ;
    SHAPE ABUTMENT ;
    PORT
      LAYER M4 ;
      RECT 52.272 30.720 52.296 30.744 ;
    END
  END w_mask_in[85]
  PIN w_mask_in[86]
    DIRECTION INPUT ;
    USE SIGNAL ;
    SHAPE ABUTMENT ;
    PORT
      LAYER M4 ;
      RECT 52.272 30.912 52.296 30.936 ;
    END
  END w_mask_in[86]
  PIN w_mask_in[87]
    DIRECTION INPUT ;
    USE SIGNAL ;
    SHAPE ABUTMENT ;
    PORT
      LAYER M4 ;
      RECT 52.272 31.104 52.296 31.128 ;
    END
  END w_mask_in[87]
  PIN w_mask_in[88]
    DIRECTION INPUT ;
    USE SIGNAL ;
    SHAPE ABUTMENT ;
    PORT
      LAYER M4 ;
      RECT 52.272 31.296 52.296 31.320 ;
    END
  END w_mask_in[88]
  PIN w_mask_in[89]
    DIRECTION INPUT ;
    USE SIGNAL ;
    SHAPE ABUTMENT ;
    PORT
      LAYER M4 ;
      RECT 52.272 31.488 52.296 31.512 ;
    END
  END w_mask_in[89]
  PIN w_mask_in[90]
    DIRECTION INPUT ;
    USE SIGNAL ;
    SHAPE ABUTMENT ;
    PORT
      LAYER M4 ;
      RECT 52.272 31.680 52.296 31.704 ;
    END
  END w_mask_in[90]
  PIN w_mask_in[91]
    DIRECTION INPUT ;
    USE SIGNAL ;
    SHAPE ABUTMENT ;
    PORT
      LAYER M4 ;
      RECT 52.272 31.872 52.296 31.896 ;
    END
  END w_mask_in[91]
  PIN w_mask_in[92]
    DIRECTION INPUT ;
    USE SIGNAL ;
    SHAPE ABUTMENT ;
    PORT
      LAYER M4 ;
      RECT 52.272 32.064 52.296 32.088 ;
    END
  END w_mask_in[92]
  PIN w_mask_in[93]
    DIRECTION INPUT ;
    USE SIGNAL ;
    SHAPE ABUTMENT ;
    PORT
      LAYER M4 ;
      RECT 52.272 32.256 52.296 32.280 ;
    END
  END w_mask_in[93]
  PIN w_mask_in[94]
    DIRECTION INPUT ;
    USE SIGNAL ;
    SHAPE ABUTMENT ;
    PORT
      LAYER M4 ;
      RECT 52.272 32.448 52.296 32.472 ;
    END
  END w_mask_in[94]
  PIN w_mask_in[95]
    DIRECTION INPUT ;
    USE SIGNAL ;
    SHAPE ABUTMENT ;
    PORT
      LAYER M4 ;
      RECT 52.272 32.640 52.296 32.664 ;
    END
  END w_mask_in[95]
  PIN w_mask_in[96]
    DIRECTION INPUT ;
    USE SIGNAL ;
    SHAPE ABUTMENT ;
    PORT
      LAYER M4 ;
      RECT 52.272 32.832 52.296 32.856 ;
    END
  END w_mask_in[96]
  PIN w_mask_in[97]
    DIRECTION INPUT ;
    USE SIGNAL ;
    SHAPE ABUTMENT ;
    PORT
      LAYER M4 ;
      RECT 52.272 33.024 52.296 33.048 ;
    END
  END w_mask_in[97]
  PIN w_mask_in[98]
    DIRECTION INPUT ;
    USE SIGNAL ;
    SHAPE ABUTMENT ;
    PORT
      LAYER M4 ;
      RECT 52.272 33.216 52.296 33.240 ;
    END
  END w_mask_in[98]
  PIN w_mask_in[99]
    DIRECTION INPUT ;
    USE SIGNAL ;
    SHAPE ABUTMENT ;
    PORT
      LAYER M4 ;
      RECT 52.272 33.408 52.296 33.432 ;
    END
  END w_mask_in[99]
  PIN w_mask_in[100]
    DIRECTION INPUT ;
    USE SIGNAL ;
    SHAPE ABUTMENT ;
    PORT
      LAYER M4 ;
      RECT 52.272 33.600 52.296 33.624 ;
    END
  END w_mask_in[100]
  PIN w_mask_in[101]
    DIRECTION INPUT ;
    USE SIGNAL ;
    SHAPE ABUTMENT ;
    PORT
      LAYER M4 ;
      RECT 52.272 33.792 52.296 33.816 ;
    END
  END w_mask_in[101]
  PIN w_mask_in[102]
    DIRECTION INPUT ;
    USE SIGNAL ;
    SHAPE ABUTMENT ;
    PORT
      LAYER M4 ;
      RECT 52.272 33.984 52.296 34.008 ;
    END
  END w_mask_in[102]
  PIN w_mask_in[103]
    DIRECTION INPUT ;
    USE SIGNAL ;
    SHAPE ABUTMENT ;
    PORT
      LAYER M4 ;
      RECT 52.272 34.176 52.296 34.200 ;
    END
  END w_mask_in[103]
  PIN w_mask_in[104]
    DIRECTION INPUT ;
    USE SIGNAL ;
    SHAPE ABUTMENT ;
    PORT
      LAYER M4 ;
      RECT 52.272 34.368 52.296 34.392 ;
    END
  END w_mask_in[104]
  PIN w_mask_in[105]
    DIRECTION INPUT ;
    USE SIGNAL ;
    SHAPE ABUTMENT ;
    PORT
      LAYER M4 ;
      RECT 52.272 34.560 52.296 34.584 ;
    END
  END w_mask_in[105]
  PIN w_mask_in[106]
    DIRECTION INPUT ;
    USE SIGNAL ;
    SHAPE ABUTMENT ;
    PORT
      LAYER M4 ;
      RECT 52.272 34.752 52.296 34.776 ;
    END
  END w_mask_in[106]
  PIN w_mask_in[107]
    DIRECTION INPUT ;
    USE SIGNAL ;
    SHAPE ABUTMENT ;
    PORT
      LAYER M4 ;
      RECT 52.272 34.944 52.296 34.968 ;
    END
  END w_mask_in[107]
  PIN w_mask_in[108]
    DIRECTION INPUT ;
    USE SIGNAL ;
    SHAPE ABUTMENT ;
    PORT
      LAYER M4 ;
      RECT 52.272 35.136 52.296 35.160 ;
    END
  END w_mask_in[108]
  PIN w_mask_in[109]
    DIRECTION INPUT ;
    USE SIGNAL ;
    SHAPE ABUTMENT ;
    PORT
      LAYER M4 ;
      RECT 52.272 35.328 52.296 35.352 ;
    END
  END w_mask_in[109]
  PIN w_mask_in[110]
    DIRECTION INPUT ;
    USE SIGNAL ;
    SHAPE ABUTMENT ;
    PORT
      LAYER M4 ;
      RECT 52.272 35.520 52.296 35.544 ;
    END
  END w_mask_in[110]
  PIN w_mask_in[111]
    DIRECTION INPUT ;
    USE SIGNAL ;
    SHAPE ABUTMENT ;
    PORT
      LAYER M4 ;
      RECT 52.272 35.712 52.296 35.736 ;
    END
  END w_mask_in[111]
  PIN w_mask_in[112]
    DIRECTION INPUT ;
    USE SIGNAL ;
    SHAPE ABUTMENT ;
    PORT
      LAYER M4 ;
      RECT 52.272 35.904 52.296 35.928 ;
    END
  END w_mask_in[112]
  PIN w_mask_in[113]
    DIRECTION INPUT ;
    USE SIGNAL ;
    SHAPE ABUTMENT ;
    PORT
      LAYER M4 ;
      RECT 52.272 36.096 52.296 36.120 ;
    END
  END w_mask_in[113]
  PIN w_mask_in[114]
    DIRECTION INPUT ;
    USE SIGNAL ;
    SHAPE ABUTMENT ;
    PORT
      LAYER M4 ;
      RECT 52.272 36.288 52.296 36.312 ;
    END
  END w_mask_in[114]
  PIN w_mask_in[115]
    DIRECTION INPUT ;
    USE SIGNAL ;
    SHAPE ABUTMENT ;
    PORT
      LAYER M4 ;
      RECT 52.272 36.480 52.296 36.504 ;
    END
  END w_mask_in[115]
  PIN w_mask_in[116]
    DIRECTION INPUT ;
    USE SIGNAL ;
    SHAPE ABUTMENT ;
    PORT
      LAYER M4 ;
      RECT 52.272 36.672 52.296 36.696 ;
    END
  END w_mask_in[116]
  PIN w_mask_in[117]
    DIRECTION INPUT ;
    USE SIGNAL ;
    SHAPE ABUTMENT ;
    PORT
      LAYER M4 ;
      RECT 52.272 36.864 52.296 36.888 ;
    END
  END w_mask_in[117]
  PIN w_mask_in[118]
    DIRECTION INPUT ;
    USE SIGNAL ;
    SHAPE ABUTMENT ;
    PORT
      LAYER M4 ;
      RECT 52.272 37.056 52.296 37.080 ;
    END
  END w_mask_in[118]
  PIN w_mask_in[119]
    DIRECTION INPUT ;
    USE SIGNAL ;
    SHAPE ABUTMENT ;
    PORT
      LAYER M4 ;
      RECT 52.272 37.248 52.296 37.272 ;
    END
  END w_mask_in[119]
  PIN w_mask_in[120]
    DIRECTION INPUT ;
    USE SIGNAL ;
    SHAPE ABUTMENT ;
    PORT
      LAYER M4 ;
      RECT 52.272 37.440 52.296 37.464 ;
    END
  END w_mask_in[120]
  PIN w_mask_in[121]
    DIRECTION INPUT ;
    USE SIGNAL ;
    SHAPE ABUTMENT ;
    PORT
      LAYER M4 ;
      RECT 52.272 37.632 52.296 37.656 ;
    END
  END w_mask_in[121]
  PIN w_mask_in[122]
    DIRECTION INPUT ;
    USE SIGNAL ;
    SHAPE ABUTMENT ;
    PORT
      LAYER M4 ;
      RECT 52.272 37.824 52.296 37.848 ;
    END
  END w_mask_in[122]
  PIN w_mask_in[123]
    DIRECTION INPUT ;
    USE SIGNAL ;
    SHAPE ABUTMENT ;
    PORT
      LAYER M4 ;
      RECT 52.272 38.016 52.296 38.040 ;
    END
  END w_mask_in[123]
  PIN w_mask_in[124]
    DIRECTION INPUT ;
    USE SIGNAL ;
    SHAPE ABUTMENT ;
    PORT
      LAYER M4 ;
      RECT 52.272 38.208 52.296 38.232 ;
    END
  END w_mask_in[124]
  PIN w_mask_in[125]
    DIRECTION INPUT ;
    USE SIGNAL ;
    SHAPE ABUTMENT ;
    PORT
      LAYER M4 ;
      RECT 52.272 38.400 52.296 38.424 ;
    END
  END w_mask_in[125]
  PIN w_mask_in[126]
    DIRECTION INPUT ;
    USE SIGNAL ;
    SHAPE ABUTMENT ;
    PORT
      LAYER M4 ;
      RECT 52.272 38.592 52.296 38.616 ;
    END
  END w_mask_in[126]
  PIN w_mask_in[127]
    DIRECTION INPUT ;
    USE SIGNAL ;
    SHAPE ABUTMENT ;
    PORT
      LAYER M4 ;
      RECT 52.272 38.784 52.296 38.808 ;
    END
  END w_mask_in[127]
  PIN VDD
    DIRECTION INOUT ;
    USE POWER ;
    PORT
      LAYER M4 ;
      RECT 0.300 0.384 51.996 0.480 ;
      RECT 0.300 1.152 51.996 1.248 ;
      RECT 0.300 1.920 51.996 2.016 ;
      RECT 0.300 2.688 51.996 2.784 ;
      RECT 0.300 3.456 51.996 3.552 ;
      RECT 0.300 4.224 51.996 4.320 ;
      RECT 0.300 4.992 51.996 5.088 ;
      RECT 0.300 5.760 51.996 5.856 ;
      RECT 0.300 6.528 51.996 6.624 ;
      RECT 0.300 7.296 51.996 7.392 ;
      RECT 0.300 8.064 51.996 8.160 ;
      RECT 0.300 8.832 51.996 8.928 ;
      RECT 0.300 9.600 51.996 9.696 ;
      RECT 0.300 10.368 51.996 10.464 ;
      RECT 0.300 11.136 51.996 11.232 ;
      RECT 0.300 11.904 51.996 12.000 ;
      RECT 0.300 12.672 51.996 12.768 ;
      RECT 0.300 13.440 51.996 13.536 ;
      RECT 0.300 14.208 51.996 14.304 ;
      RECT 0.300 14.976 51.996 15.072 ;
      RECT 0.300 15.744 51.996 15.840 ;
      RECT 0.300 16.512 51.996 16.608 ;
      RECT 0.300 17.280 51.996 17.376 ;
      RECT 0.300 18.048 51.996 18.144 ;
      RECT 0.300 18.816 51.996 18.912 ;
      RECT 0.300 19.584 51.996 19.680 ;
      RECT 0.300 20.352 51.996 20.448 ;
      RECT 0.300 21.120 51.996 21.216 ;
      RECT 0.300 21.888 51.996 21.984 ;
      RECT 0.300 22.656 51.996 22.752 ;
      RECT 0.300 23.424 51.996 23.520 ;
      RECT 0.300 24.192 51.996 24.288 ;
      RECT 0.300 24.960 51.996 25.056 ;
      RECT 0.300 25.728 51.996 25.824 ;
      RECT 0.300 26.496 51.996 26.592 ;
      RECT 0.300 27.264 51.996 27.360 ;
      RECT 0.300 28.032 51.996 28.128 ;
      RECT 0.300 28.800 51.996 28.896 ;
      RECT 0.300 29.568 51.996 29.664 ;
      RECT 0.300 30.336 51.996 30.432 ;
      RECT 0.300 31.104 51.996 31.200 ;
      RECT 0.300 31.872 51.996 31.968 ;
      RECT 0.300 32.640 51.996 32.736 ;
      RECT 0.300 33.408 51.996 33.504 ;
      RECT 0.300 34.176 51.996 34.272 ;
      RECT 0.300 34.944 51.996 35.040 ;
      RECT 0.300 35.712 51.996 35.808 ;
      RECT 0.300 36.480 51.996 36.576 ;
      RECT 0.300 37.248 51.996 37.344 ;
      RECT 0.300 38.016 51.996 38.112 ;
      RECT 0.300 38.784 51.996 38.880 ;
      RECT 0.300 39.552 51.996 39.648 ;
    END
  END VDD
  PIN VSS
    DIRECTION INOUT ;
    USE GROUND ;
    PORT
      LAYER M4 ;
      RECT 0.300 0.768 51.996 0.864 ;
      RECT 0.300 1.536 51.996 1.632 ;
      RECT 0.300 2.304 51.996 2.400 ;
      RECT 0.300 3.072 51.996 3.168 ;
      RECT 0.300 3.840 51.996 3.936 ;
      RECT 0.300 4.608 51.996 4.704 ;
      RECT 0.300 5.376 51.996 5.472 ;
      RECT 0.300 6.144 51.996 6.240 ;
      RECT 0.300 6.912 51.996 7.008 ;
      RECT 0.300 7.680 51.996 7.776 ;
      RECT 0.300 8.448 51.996 8.544 ;
      RECT 0.300 9.216 51.996 9.312 ;
      RECT 0.300 9.984 51.996 10.080 ;
      RECT 0.300 10.752 51.996 10.848 ;
      RECT 0.300 11.520 51.996 11.616 ;
      RECT 0.300 12.288 51.996 12.384 ;
      RECT 0.300 13.056 51.996 13.152 ;
      RECT 0.300 13.824 51.996 13.920 ;
      RECT 0.300 14.592 51.996 14.688 ;
      RECT 0.300 15.360 51.996 15.456 ;
      RECT 0.300 16.128 51.996 16.224 ;
      RECT 0.300 16.896 51.996 16.992 ;
      RECT 0.300 17.664 51.996 17.760 ;
      RECT 0.300 18.432 51.996 18.528 ;
      RECT 0.300 19.200 51.996 19.296 ;
      RECT 0.300 19.968 51.996 20.064 ;
      RECT 0.300 20.736 51.996 20.832 ;
      RECT 0.300 21.504 51.996 21.600 ;
      RECT 0.300 22.272 51.996 22.368 ;
      RECT 0.300 23.040 51.996 23.136 ;
      RECT 0.300 23.808 51.996 23.904 ;
      RECT 0.300 24.576 51.996 24.672 ;
      RECT 0.300 25.344 51.996 25.440 ;
      RECT 0.300 26.112 51.996 26.208 ;
      RECT 0.300 26.880 51.996 26.976 ;
      RECT 0.300 27.648 51.996 27.744 ;
      RECT 0.300 28.416 51.996 28.512 ;
      RECT 0.300 29.184 51.996 29.280 ;
      RECT 0.300 29.952 51.996 30.048 ;
      RECT 0.300 30.720 51.996 30.816 ;
      RECT 0.300 31.488 51.996 31.584 ;
      RECT 0.300 32.256 51.996 32.352 ;
      RECT 0.300 33.024 51.996 33.120 ;
      RECT 0.300 33.792 51.996 33.888 ;
      RECT 0.300 34.560 51.996 34.656 ;
      RECT 0.300 35.328 51.996 35.424 ;
      RECT 0.300 36.096 51.996 36.192 ;
      RECT 0.300 36.864 51.996 36.960 ;
      RECT 0.300 37.632 51.996 37.728 ;
      RECT 0.300 38.400 51.996 38.496 ;
      RECT 0.300 39.168 51.996 39.264 ;
    END
  END VSS
  OBS
    LAYER M1 ;
    RECT 0 0 52.296 39.960 ;
    LAYER M2 ;
    RECT 0 0 52.296 39.960 ;
    LAYER M3 ;
    RECT 0 0 52.296 39.960 ;
    LAYER M4 ;
    RECT 0.072 0 52.224 39.960 ;
  END
END ctl_sram_1r1w_64x128_p192

END LIBRARY
